VERSION 5.7 ;
  NOWIREEXTENSIONATPIN ON ;
  DIVIDERCHAR "/" ;
  BUSBITCHARS "[]" ;
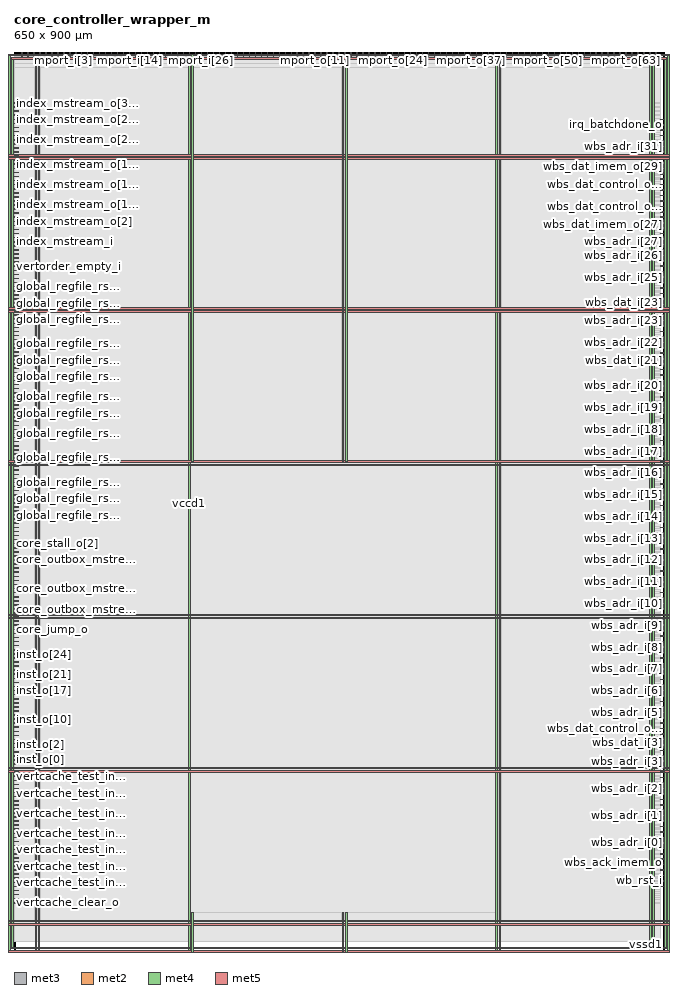
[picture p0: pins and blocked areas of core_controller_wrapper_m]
MACRO core_controller_wrapper_m
  CLASS BLOCK ;
  FOREIGN core_controller_wrapper_m ;
  ORIGIN 0.000 0.000 ;
  SIZE 650.000 BY 900.000 ;
  PIN core_inbox_mstream_i[0]
    DIRECTION INPUT ;
    USE SIGNAL ;
    ANTENNAGATEAREA 0.247500 ;
    PORT
      LAYER met3 ;
        RECT 0.000 326.440 4.000 327.040 ;
    END
  END core_inbox_mstream_i[0]
  PIN core_inbox_mstream_i[1]
    DIRECTION INPUT ;
    USE SIGNAL ;
    ANTENNAGATEAREA 0.247500 ;
    PORT
      LAYER met3 ;
        RECT 0.000 355.000 4.000 355.600 ;
    END
  END core_inbox_mstream_i[1]
  PIN core_inbox_mstream_i[2]
    DIRECTION INPUT ;
    USE SIGNAL ;
    ANTENNAGATEAREA 0.247500 ;
    PORT
      LAYER met3 ;
        RECT 0.000 383.560 4.000 384.160 ;
    END
  END core_inbox_mstream_i[2]
  PIN core_jump_i[0]
    DIRECTION INPUT ;
    USE SIGNAL ;
    ANTENNAGATEAREA 0.196500 ;
    PORT
      LAYER met3 ;
        RECT 0.000 330.520 4.000 331.120 ;
    END
  END core_jump_i[0]
  PIN core_jump_i[1]
    DIRECTION INPUT ;
    USE SIGNAL ;
    ANTENNAGATEAREA 0.196500 ;
    PORT
      LAYER met3 ;
        RECT 0.000 359.080 4.000 359.680 ;
    END
  END core_jump_i[1]
  PIN core_jump_i[2]
    DIRECTION INPUT ;
    USE SIGNAL ;
    ANTENNAGATEAREA 0.196500 ;
    PORT
      LAYER met3 ;
        RECT 0.000 387.640 4.000 388.240 ;
    END
  END core_jump_i[2]
  PIN core_jump_o
    DIRECTION OUTPUT TRISTATE ;
    USE SIGNAL ;
    ANTENNADIFFAREA 0.795200 ;
    PORT
      LAYER met3 ;
        RECT 0.000 322.360 4.000 322.960 ;
    END
  END core_jump_o
  PIN core_outbox_mstream_valid_i[0]
    DIRECTION INPUT ;
    USE SIGNAL ;
    ANTENNAGATEAREA 0.196500 ;
    PORT
      LAYER met3 ;
        RECT 0.000 334.600 4.000 335.200 ;
    END
  END core_outbox_mstream_valid_i[0]
  PIN core_outbox_mstream_valid_i[1]
    DIRECTION INPUT ;
    USE SIGNAL ;
    ANTENNAGATEAREA 0.196500 ;
    PORT
      LAYER met3 ;
        RECT 0.000 363.160 4.000 363.760 ;
    END
  END core_outbox_mstream_valid_i[1]
  PIN core_outbox_mstream_valid_i[2]
    DIRECTION INPUT ;
    USE SIGNAL ;
    ANTENNAGATEAREA 0.196500 ;
    PORT
      LAYER met3 ;
        RECT 0.000 391.720 4.000 392.320 ;
    END
  END core_outbox_mstream_valid_i[2]
  PIN core_reset_mailbox_o[0]
    DIRECTION OUTPUT TRISTATE ;
    USE SIGNAL ;
    ANTENNADIFFAREA 0.795200 ;
    PORT
      LAYER met3 ;
        RECT 0.000 338.680 4.000 339.280 ;
    END
  END core_reset_mailbox_o[0]
  PIN core_reset_mailbox_o[1]
    DIRECTION OUTPUT TRISTATE ;
    USE SIGNAL ;
    ANTENNADIFFAREA 0.795200 ;
    PORT
      LAYER met3 ;
        RECT 0.000 367.240 4.000 367.840 ;
    END
  END core_reset_mailbox_o[1]
  PIN core_reset_mailbox_o[2]
    DIRECTION OUTPUT TRISTATE ;
    USE SIGNAL ;
    ANTENNADIFFAREA 0.795200 ;
    PORT
      LAYER met3 ;
        RECT 0.000 395.800 4.000 396.400 ;
    END
  END core_reset_mailbox_o[2]
  PIN core_reset_o[0]
    DIRECTION OUTPUT TRISTATE ;
    USE SIGNAL ;
    ANTENNADIFFAREA 0.795200 ;
    PORT
      LAYER met3 ;
        RECT 0.000 342.760 4.000 343.360 ;
    END
  END core_reset_o[0]
  PIN core_reset_o[1]
    DIRECTION OUTPUT TRISTATE ;
    USE SIGNAL ;
    ANTENNADIFFAREA 0.795200 ;
    PORT
      LAYER met3 ;
        RECT 0.000 371.320 4.000 371.920 ;
    END
  END core_reset_o[1]
  PIN core_reset_o[2]
    DIRECTION OUTPUT TRISTATE ;
    USE SIGNAL ;
    ANTENNADIFFAREA 0.795200 ;
    PORT
      LAYER met3 ;
        RECT 0.000 399.880 4.000 400.480 ;
    END
  END core_reset_o[2]
  PIN core_stall_i[0]
    DIRECTION INPUT ;
    USE SIGNAL ;
    ANTENNAGATEAREA 0.196500 ;
    PORT
      LAYER met3 ;
        RECT 0.000 346.840 4.000 347.440 ;
    END
  END core_stall_i[0]
  PIN core_stall_i[1]
    DIRECTION INPUT ;
    USE SIGNAL ;
    ANTENNAGATEAREA 0.196500 ;
    PORT
      LAYER met3 ;
        RECT 0.000 375.400 4.000 376.000 ;
    END
  END core_stall_i[1]
  PIN core_stall_i[2]
    DIRECTION INPUT ;
    USE SIGNAL ;
    ANTENNAGATEAREA 0.196500 ;
    PORT
      LAYER met3 ;
        RECT 0.000 403.960 4.000 404.560 ;
    END
  END core_stall_i[2]
  PIN core_stall_o[0]
    DIRECTION OUTPUT TRISTATE ;
    USE SIGNAL ;
    ANTENNADIFFAREA 0.795200 ;
    PORT
      LAYER met3 ;
        RECT 0.000 350.920 4.000 351.520 ;
    END
  END core_stall_o[0]
  PIN core_stall_o[1]
    DIRECTION OUTPUT TRISTATE ;
    USE SIGNAL ;
    ANTENNADIFFAREA 0.795200 ;
    PORT
      LAYER met3 ;
        RECT 0.000 379.480 4.000 380.080 ;
    END
  END core_stall_o[1]
  PIN core_stall_o[2]
    DIRECTION OUTPUT TRISTATE ;
    USE SIGNAL ;
    ANTENNADIFFAREA 0.795200 ;
    PORT
      LAYER met3 ;
        RECT 0.000 408.040 4.000 408.640 ;
    END
  END core_stall_o[2]
  PIN fragfifo_clear_o
    DIRECTION OUTPUT TRISTATE ;
    USE SIGNAL ;
    ANTENNADIFFAREA 0.795200 ;
    PORT
      LAYER met2 ;
        RECT 7.910 896.000 8.190 900.000 ;
    END
  END fragfifo_clear_o
  PIN fragfifo_empty_i
    DIRECTION INPUT ;
    USE SIGNAL ;
    ANTENNAGATEAREA 0.126000 ;
    PORT
      LAYER met2 ;
        RECT 13.890 896.000 14.170 900.000 ;
    END
  END fragfifo_empty_i
  PIN fragfifo_full_i
    DIRECTION INPUT ;
    USE SIGNAL ;
    PORT
      LAYER met2 ;
        RECT 19.870 896.000 20.150 900.000 ;
    END
  END fragfifo_full_i
  PIN global_regfile_rs1_data_o[0]
    DIRECTION OUTPUT TRISTATE ;
    USE SIGNAL ;
    ANTENNADIFFAREA 0.795200 ;
    PORT
      LAYER met3 ;
        RECT 0.000 412.120 4.000 412.720 ;
    END
  END global_regfile_rs1_data_o[0]
  PIN global_regfile_rs1_data_o[10]
    DIRECTION OUTPUT TRISTATE ;
    USE SIGNAL ;
    ANTENNADIFFAREA 0.795200 ;
    PORT
      LAYER met3 ;
        RECT 0.000 493.720 4.000 494.320 ;
    END
  END global_regfile_rs1_data_o[10]
  PIN global_regfile_rs1_data_o[11]
    DIRECTION OUTPUT TRISTATE ;
    USE SIGNAL ;
    ANTENNADIFFAREA 0.795200 ;
    PORT
      LAYER met3 ;
        RECT 0.000 501.880 4.000 502.480 ;
    END
  END global_regfile_rs1_data_o[11]
  PIN global_regfile_rs1_data_o[12]
    DIRECTION OUTPUT TRISTATE ;
    USE SIGNAL ;
    ANTENNADIFFAREA 0.795200 ;
    PORT
      LAYER met3 ;
        RECT 0.000 510.040 4.000 510.640 ;
    END
  END global_regfile_rs1_data_o[12]
  PIN global_regfile_rs1_data_o[13]
    DIRECTION OUTPUT TRISTATE ;
    USE SIGNAL ;
    ANTENNADIFFAREA 0.795200 ;
    PORT
      LAYER met3 ;
        RECT 0.000 518.200 4.000 518.800 ;
    END
  END global_regfile_rs1_data_o[13]
  PIN global_regfile_rs1_data_o[14]
    DIRECTION OUTPUT TRISTATE ;
    USE SIGNAL ;
    ANTENNADIFFAREA 0.795200 ;
    PORT
      LAYER met3 ;
        RECT 0.000 526.360 4.000 526.960 ;
    END
  END global_regfile_rs1_data_o[14]
  PIN global_regfile_rs1_data_o[15]
    DIRECTION OUTPUT TRISTATE ;
    USE SIGNAL ;
    ANTENNADIFFAREA 0.795200 ;
    PORT
      LAYER met3 ;
        RECT 0.000 534.520 4.000 535.120 ;
    END
  END global_regfile_rs1_data_o[15]
  PIN global_regfile_rs1_data_o[16]
    DIRECTION OUTPUT TRISTATE ;
    USE SIGNAL ;
    ANTENNADIFFAREA 0.795200 ;
    PORT
      LAYER met3 ;
        RECT 0.000 542.680 4.000 543.280 ;
    END
  END global_regfile_rs1_data_o[16]
  PIN global_regfile_rs1_data_o[17]
    DIRECTION OUTPUT TRISTATE ;
    USE SIGNAL ;
    ANTENNADIFFAREA 0.795200 ;
    PORT
      LAYER met3 ;
        RECT 0.000 550.840 4.000 551.440 ;
    END
  END global_regfile_rs1_data_o[17]
  PIN global_regfile_rs1_data_o[18]
    DIRECTION OUTPUT TRISTATE ;
    USE SIGNAL ;
    ANTENNADIFFAREA 0.795200 ;
    PORT
      LAYER met3 ;
        RECT 0.000 559.000 4.000 559.600 ;
    END
  END global_regfile_rs1_data_o[18]
  PIN global_regfile_rs1_data_o[19]
    DIRECTION OUTPUT TRISTATE ;
    USE SIGNAL ;
    ANTENNADIFFAREA 0.795200 ;
    PORT
      LAYER met3 ;
        RECT 0.000 567.160 4.000 567.760 ;
    END
  END global_regfile_rs1_data_o[19]
  PIN global_regfile_rs1_data_o[1]
    DIRECTION OUTPUT TRISTATE ;
    USE SIGNAL ;
    ANTENNADIFFAREA 0.795200 ;
    PORT
      LAYER met3 ;
        RECT 0.000 420.280 4.000 420.880 ;
    END
  END global_regfile_rs1_data_o[1]
  PIN global_regfile_rs1_data_o[20]
    DIRECTION OUTPUT TRISTATE ;
    USE SIGNAL ;
    ANTENNADIFFAREA 0.795200 ;
    PORT
      LAYER met3 ;
        RECT 0.000 575.320 4.000 575.920 ;
    END
  END global_regfile_rs1_data_o[20]
  PIN global_regfile_rs1_data_o[21]
    DIRECTION OUTPUT TRISTATE ;
    USE SIGNAL ;
    ANTENNADIFFAREA 0.795200 ;
    PORT
      LAYER met3 ;
        RECT 0.000 583.480 4.000 584.080 ;
    END
  END global_regfile_rs1_data_o[21]
  PIN global_regfile_rs1_data_o[22]
    DIRECTION OUTPUT TRISTATE ;
    USE SIGNAL ;
    ANTENNADIFFAREA 0.795200 ;
    PORT
      LAYER met3 ;
        RECT 0.000 591.640 4.000 592.240 ;
    END
  END global_regfile_rs1_data_o[22]
  PIN global_regfile_rs1_data_o[23]
    DIRECTION OUTPUT TRISTATE ;
    USE SIGNAL ;
    ANTENNADIFFAREA 0.795200 ;
    PORT
      LAYER met3 ;
        RECT 0.000 599.800 4.000 600.400 ;
    END
  END global_regfile_rs1_data_o[23]
  PIN global_regfile_rs1_data_o[24]
    DIRECTION OUTPUT TRISTATE ;
    USE SIGNAL ;
    ANTENNADIFFAREA 0.795200 ;
    PORT
      LAYER met3 ;
        RECT 0.000 607.960 4.000 608.560 ;
    END
  END global_regfile_rs1_data_o[24]
  PIN global_regfile_rs1_data_o[25]
    DIRECTION OUTPUT TRISTATE ;
    USE SIGNAL ;
    ANTENNADIFFAREA 0.795200 ;
    PORT
      LAYER met3 ;
        RECT 0.000 616.120 4.000 616.720 ;
    END
  END global_regfile_rs1_data_o[25]
  PIN global_regfile_rs1_data_o[26]
    DIRECTION OUTPUT TRISTATE ;
    USE SIGNAL ;
    ANTENNADIFFAREA 0.795200 ;
    PORT
      LAYER met3 ;
        RECT 0.000 624.280 4.000 624.880 ;
    END
  END global_regfile_rs1_data_o[26]
  PIN global_regfile_rs1_data_o[27]
    DIRECTION OUTPUT TRISTATE ;
    USE SIGNAL ;
    ANTENNADIFFAREA 0.795200 ;
    PORT
      LAYER met3 ;
        RECT 0.000 632.440 4.000 633.040 ;
    END
  END global_regfile_rs1_data_o[27]
  PIN global_regfile_rs1_data_o[28]
    DIRECTION OUTPUT TRISTATE ;
    USE SIGNAL ;
    ANTENNADIFFAREA 0.795200 ;
    PORT
      LAYER met3 ;
        RECT 0.000 640.600 4.000 641.200 ;
    END
  END global_regfile_rs1_data_o[28]
  PIN global_regfile_rs1_data_o[29]
    DIRECTION OUTPUT TRISTATE ;
    USE SIGNAL ;
    ANTENNADIFFAREA 0.795200 ;
    PORT
      LAYER met3 ;
        RECT 0.000 648.760 4.000 649.360 ;
    END
  END global_regfile_rs1_data_o[29]
  PIN global_regfile_rs1_data_o[2]
    DIRECTION OUTPUT TRISTATE ;
    USE SIGNAL ;
    ANTENNADIFFAREA 0.795200 ;
    PORT
      LAYER met3 ;
        RECT 0.000 428.440 4.000 429.040 ;
    END
  END global_regfile_rs1_data_o[2]
  PIN global_regfile_rs1_data_o[30]
    DIRECTION OUTPUT TRISTATE ;
    USE SIGNAL ;
    ANTENNADIFFAREA 0.795200 ;
    PORT
      LAYER met3 ;
        RECT 0.000 656.920 4.000 657.520 ;
    END
  END global_regfile_rs1_data_o[30]
  PIN global_regfile_rs1_data_o[31]
    DIRECTION OUTPUT TRISTATE ;
    USE SIGNAL ;
    ANTENNADIFFAREA 0.795200 ;
    PORT
      LAYER met3 ;
        RECT 0.000 665.080 4.000 665.680 ;
    END
  END global_regfile_rs1_data_o[31]
  PIN global_regfile_rs1_data_o[3]
    DIRECTION OUTPUT TRISTATE ;
    USE SIGNAL ;
    ANTENNADIFFAREA 0.795200 ;
    PORT
      LAYER met3 ;
        RECT 0.000 436.600 4.000 437.200 ;
    END
  END global_regfile_rs1_data_o[3]
  PIN global_regfile_rs1_data_o[4]
    DIRECTION OUTPUT TRISTATE ;
    USE SIGNAL ;
    ANTENNADIFFAREA 0.795200 ;
    PORT
      LAYER met3 ;
        RECT 0.000 444.760 4.000 445.360 ;
    END
  END global_regfile_rs1_data_o[4]
  PIN global_regfile_rs1_data_o[5]
    DIRECTION OUTPUT TRISTATE ;
    USE SIGNAL ;
    ANTENNADIFFAREA 0.795200 ;
    PORT
      LAYER met3 ;
        RECT 0.000 452.920 4.000 453.520 ;
    END
  END global_regfile_rs1_data_o[5]
  PIN global_regfile_rs1_data_o[6]
    DIRECTION OUTPUT TRISTATE ;
    USE SIGNAL ;
    ANTENNADIFFAREA 0.795200 ;
    PORT
      LAYER met3 ;
        RECT 0.000 461.080 4.000 461.680 ;
    END
  END global_regfile_rs1_data_o[6]
  PIN global_regfile_rs1_data_o[7]
    DIRECTION OUTPUT TRISTATE ;
    USE SIGNAL ;
    ANTENNADIFFAREA 0.795200 ;
    PORT
      LAYER met3 ;
        RECT 0.000 469.240 4.000 469.840 ;
    END
  END global_regfile_rs1_data_o[7]
  PIN global_regfile_rs1_data_o[8]
    DIRECTION OUTPUT TRISTATE ;
    USE SIGNAL ;
    ANTENNADIFFAREA 0.795200 ;
    PORT
      LAYER met3 ;
        RECT 0.000 477.400 4.000 478.000 ;
    END
  END global_regfile_rs1_data_o[8]
  PIN global_regfile_rs1_data_o[9]
    DIRECTION OUTPUT TRISTATE ;
    USE SIGNAL ;
    ANTENNADIFFAREA 0.795200 ;
    PORT
      LAYER met3 ;
        RECT 0.000 485.560 4.000 486.160 ;
    END
  END global_regfile_rs1_data_o[9]
  PIN global_regfile_rs2_data_o[0]
    DIRECTION OUTPUT TRISTATE ;
    USE SIGNAL ;
    ANTENNADIFFAREA 0.795200 ;
    PORT
      LAYER met3 ;
        RECT 0.000 416.200 4.000 416.800 ;
    END
  END global_regfile_rs2_data_o[0]
  PIN global_regfile_rs2_data_o[10]
    DIRECTION OUTPUT TRISTATE ;
    USE SIGNAL ;
    ANTENNADIFFAREA 0.795200 ;
    PORT
      LAYER met3 ;
        RECT 0.000 497.800 4.000 498.400 ;
    END
  END global_regfile_rs2_data_o[10]
  PIN global_regfile_rs2_data_o[11]
    DIRECTION OUTPUT TRISTATE ;
    USE SIGNAL ;
    ANTENNADIFFAREA 0.795200 ;
    PORT
      LAYER met3 ;
        RECT 0.000 505.960 4.000 506.560 ;
    END
  END global_regfile_rs2_data_o[11]
  PIN global_regfile_rs2_data_o[12]
    DIRECTION OUTPUT TRISTATE ;
    USE SIGNAL ;
    ANTENNADIFFAREA 0.795200 ;
    PORT
      LAYER met3 ;
        RECT 0.000 514.120 4.000 514.720 ;
    END
  END global_regfile_rs2_data_o[12]
  PIN global_regfile_rs2_data_o[13]
    DIRECTION OUTPUT TRISTATE ;
    USE SIGNAL ;
    ANTENNADIFFAREA 0.795200 ;
    PORT
      LAYER met3 ;
        RECT 0.000 522.280 4.000 522.880 ;
    END
  END global_regfile_rs2_data_o[13]
  PIN global_regfile_rs2_data_o[14]
    DIRECTION OUTPUT TRISTATE ;
    USE SIGNAL ;
    ANTENNADIFFAREA 0.795200 ;
    PORT
      LAYER met3 ;
        RECT 0.000 530.440 4.000 531.040 ;
    END
  END global_regfile_rs2_data_o[14]
  PIN global_regfile_rs2_data_o[15]
    DIRECTION OUTPUT TRISTATE ;
    USE SIGNAL ;
    ANTENNADIFFAREA 0.795200 ;
    PORT
      LAYER met3 ;
        RECT 0.000 538.600 4.000 539.200 ;
    END
  END global_regfile_rs2_data_o[15]
  PIN global_regfile_rs2_data_o[16]
    DIRECTION OUTPUT TRISTATE ;
    USE SIGNAL ;
    ANTENNADIFFAREA 0.795200 ;
    PORT
      LAYER met3 ;
        RECT 0.000 546.760 4.000 547.360 ;
    END
  END global_regfile_rs2_data_o[16]
  PIN global_regfile_rs2_data_o[17]
    DIRECTION OUTPUT TRISTATE ;
    USE SIGNAL ;
    ANTENNADIFFAREA 0.795200 ;
    PORT
      LAYER met3 ;
        RECT 0.000 554.920 4.000 555.520 ;
    END
  END global_regfile_rs2_data_o[17]
  PIN global_regfile_rs2_data_o[18]
    DIRECTION OUTPUT TRISTATE ;
    USE SIGNAL ;
    ANTENNADIFFAREA 0.795200 ;
    PORT
      LAYER met3 ;
        RECT 0.000 563.080 4.000 563.680 ;
    END
  END global_regfile_rs2_data_o[18]
  PIN global_regfile_rs2_data_o[19]
    DIRECTION OUTPUT TRISTATE ;
    USE SIGNAL ;
    ANTENNADIFFAREA 0.795200 ;
    PORT
      LAYER met3 ;
        RECT 0.000 571.240 4.000 571.840 ;
    END
  END global_regfile_rs2_data_o[19]
  PIN global_regfile_rs2_data_o[1]
    DIRECTION OUTPUT TRISTATE ;
    USE SIGNAL ;
    ANTENNADIFFAREA 0.795200 ;
    PORT
      LAYER met3 ;
        RECT 0.000 424.360 4.000 424.960 ;
    END
  END global_regfile_rs2_data_o[1]
  PIN global_regfile_rs2_data_o[20]
    DIRECTION OUTPUT TRISTATE ;
    USE SIGNAL ;
    ANTENNADIFFAREA 0.795200 ;
    PORT
      LAYER met3 ;
        RECT 0.000 579.400 4.000 580.000 ;
    END
  END global_regfile_rs2_data_o[20]
  PIN global_regfile_rs2_data_o[21]
    DIRECTION OUTPUT TRISTATE ;
    USE SIGNAL ;
    ANTENNADIFFAREA 0.795200 ;
    PORT
      LAYER met3 ;
        RECT 0.000 587.560 4.000 588.160 ;
    END
  END global_regfile_rs2_data_o[21]
  PIN global_regfile_rs2_data_o[22]
    DIRECTION OUTPUT TRISTATE ;
    USE SIGNAL ;
    ANTENNADIFFAREA 0.795200 ;
    PORT
      LAYER met3 ;
        RECT 0.000 595.720 4.000 596.320 ;
    END
  END global_regfile_rs2_data_o[22]
  PIN global_regfile_rs2_data_o[23]
    DIRECTION OUTPUT TRISTATE ;
    USE SIGNAL ;
    ANTENNADIFFAREA 0.795200 ;
    PORT
      LAYER met3 ;
        RECT 0.000 603.880 4.000 604.480 ;
    END
  END global_regfile_rs2_data_o[23]
  PIN global_regfile_rs2_data_o[24]
    DIRECTION OUTPUT TRISTATE ;
    USE SIGNAL ;
    ANTENNADIFFAREA 0.795200 ;
    PORT
      LAYER met3 ;
        RECT 0.000 612.040 4.000 612.640 ;
    END
  END global_regfile_rs2_data_o[24]
  PIN global_regfile_rs2_data_o[25]
    DIRECTION OUTPUT TRISTATE ;
    USE SIGNAL ;
    ANTENNADIFFAREA 0.795200 ;
    PORT
      LAYER met3 ;
        RECT 0.000 620.200 4.000 620.800 ;
    END
  END global_regfile_rs2_data_o[25]
  PIN global_regfile_rs2_data_o[26]
    DIRECTION OUTPUT TRISTATE ;
    USE SIGNAL ;
    ANTENNADIFFAREA 0.795200 ;
    PORT
      LAYER met3 ;
        RECT 0.000 628.360 4.000 628.960 ;
    END
  END global_regfile_rs2_data_o[26]
  PIN global_regfile_rs2_data_o[27]
    DIRECTION OUTPUT TRISTATE ;
    USE SIGNAL ;
    ANTENNADIFFAREA 0.795200 ;
    PORT
      LAYER met3 ;
        RECT 0.000 636.520 4.000 637.120 ;
    END
  END global_regfile_rs2_data_o[27]
  PIN global_regfile_rs2_data_o[28]
    DIRECTION OUTPUT TRISTATE ;
    USE SIGNAL ;
    ANTENNADIFFAREA 0.795200 ;
    PORT
      LAYER met3 ;
        RECT 0.000 644.680 4.000 645.280 ;
    END
  END global_regfile_rs2_data_o[28]
  PIN global_regfile_rs2_data_o[29]
    DIRECTION OUTPUT TRISTATE ;
    USE SIGNAL ;
    ANTENNADIFFAREA 0.795200 ;
    PORT
      LAYER met3 ;
        RECT 0.000 652.840 4.000 653.440 ;
    END
  END global_regfile_rs2_data_o[29]
  PIN global_regfile_rs2_data_o[2]
    DIRECTION OUTPUT TRISTATE ;
    USE SIGNAL ;
    ANTENNADIFFAREA 0.795200 ;
    PORT
      LAYER met3 ;
        RECT 0.000 432.520 4.000 433.120 ;
    END
  END global_regfile_rs2_data_o[2]
  PIN global_regfile_rs2_data_o[30]
    DIRECTION OUTPUT TRISTATE ;
    USE SIGNAL ;
    ANTENNADIFFAREA 0.795200 ;
    PORT
      LAYER met3 ;
        RECT 0.000 661.000 4.000 661.600 ;
    END
  END global_regfile_rs2_data_o[30]
  PIN global_regfile_rs2_data_o[31]
    DIRECTION OUTPUT TRISTATE ;
    USE SIGNAL ;
    ANTENNADIFFAREA 0.795200 ;
    PORT
      LAYER met3 ;
        RECT 0.000 669.160 4.000 669.760 ;
    END
  END global_regfile_rs2_data_o[31]
  PIN global_regfile_rs2_data_o[3]
    DIRECTION OUTPUT TRISTATE ;
    USE SIGNAL ;
    ANTENNADIFFAREA 0.795200 ;
    PORT
      LAYER met3 ;
        RECT 0.000 440.680 4.000 441.280 ;
    END
  END global_regfile_rs2_data_o[3]
  PIN global_regfile_rs2_data_o[4]
    DIRECTION OUTPUT TRISTATE ;
    USE SIGNAL ;
    ANTENNADIFFAREA 0.795200 ;
    PORT
      LAYER met3 ;
        RECT 0.000 448.840 4.000 449.440 ;
    END
  END global_regfile_rs2_data_o[4]
  PIN global_regfile_rs2_data_o[5]
    DIRECTION OUTPUT TRISTATE ;
    USE SIGNAL ;
    ANTENNADIFFAREA 0.795200 ;
    PORT
      LAYER met3 ;
        RECT 0.000 457.000 4.000 457.600 ;
    END
  END global_regfile_rs2_data_o[5]
  PIN global_regfile_rs2_data_o[6]
    DIRECTION OUTPUT TRISTATE ;
    USE SIGNAL ;
    ANTENNADIFFAREA 0.795200 ;
    PORT
      LAYER met3 ;
        RECT 0.000 465.160 4.000 465.760 ;
    END
  END global_regfile_rs2_data_o[6]
  PIN global_regfile_rs2_data_o[7]
    DIRECTION OUTPUT TRISTATE ;
    USE SIGNAL ;
    ANTENNADIFFAREA 0.795200 ;
    PORT
      LAYER met3 ;
        RECT 0.000 473.320 4.000 473.920 ;
    END
  END global_regfile_rs2_data_o[7]
  PIN global_regfile_rs2_data_o[8]
    DIRECTION OUTPUT TRISTATE ;
    USE SIGNAL ;
    ANTENNADIFFAREA 0.795200 ;
    PORT
      LAYER met3 ;
        RECT 0.000 481.480 4.000 482.080 ;
    END
  END global_regfile_rs2_data_o[8]
  PIN global_regfile_rs2_data_o[9]
    DIRECTION OUTPUT TRISTATE ;
    USE SIGNAL ;
    ANTENNADIFFAREA 0.795200 ;
    PORT
      LAYER met3 ;
        RECT 0.000 489.640 4.000 490.240 ;
    END
  END global_regfile_rs2_data_o[9]
  PIN index_mstream_i
    DIRECTION INPUT ;
    USE SIGNAL ;
    PORT
      LAYER met3 ;
        RECT 0.000 709.960 4.000 710.560 ;
    END
  END index_mstream_i
  PIN index_mstream_o[0]
    DIRECTION OUTPUT TRISTATE ;
    USE SIGNAL ;
    ANTENNADIFFAREA 0.795200 ;
    PORT
      LAYER met3 ;
        RECT 0.000 714.040 4.000 714.640 ;
    END
  END index_mstream_o[0]
  PIN index_mstream_o[10]
    DIRECTION OUTPUT TRISTATE ;
    USE SIGNAL ;
    ANTENNADIFFAREA 0.795200 ;
    PORT
      LAYER met3 ;
        RECT 0.000 754.840 4.000 755.440 ;
    END
  END index_mstream_o[10]
  PIN index_mstream_o[11]
    DIRECTION OUTPUT TRISTATE ;
    USE SIGNAL ;
    ANTENNADIFFAREA 0.795200 ;
    PORT
      LAYER met3 ;
        RECT 0.000 758.920 4.000 759.520 ;
    END
  END index_mstream_o[11]
  PIN index_mstream_o[12]
    DIRECTION OUTPUT TRISTATE ;
    USE SIGNAL ;
    ANTENNADIFFAREA 0.795200 ;
    PORT
      LAYER met3 ;
        RECT 0.000 763.000 4.000 763.600 ;
    END
  END index_mstream_o[12]
  PIN index_mstream_o[13]
    DIRECTION OUTPUT TRISTATE ;
    USE SIGNAL ;
    ANTENNADIFFAREA 0.795200 ;
    PORT
      LAYER met3 ;
        RECT 0.000 767.080 4.000 767.680 ;
    END
  END index_mstream_o[13]
  PIN index_mstream_o[14]
    DIRECTION OUTPUT TRISTATE ;
    USE SIGNAL ;
    ANTENNADIFFAREA 0.795200 ;
    PORT
      LAYER met3 ;
        RECT 0.000 771.160 4.000 771.760 ;
    END
  END index_mstream_o[14]
  PIN index_mstream_o[15]
    DIRECTION OUTPUT TRISTATE ;
    USE SIGNAL ;
    ANTENNADIFFAREA 0.795200 ;
    PORT
      LAYER met3 ;
        RECT 0.000 775.240 4.000 775.840 ;
    END
  END index_mstream_o[15]
  PIN index_mstream_o[16]
    DIRECTION OUTPUT TRISTATE ;
    USE SIGNAL ;
    ANTENNADIFFAREA 0.795200 ;
    PORT
      LAYER met3 ;
        RECT 0.000 779.320 4.000 779.920 ;
    END
  END index_mstream_o[16]
  PIN index_mstream_o[17]
    DIRECTION OUTPUT TRISTATE ;
    USE SIGNAL ;
    ANTENNADIFFAREA 0.795200 ;
    PORT
      LAYER met3 ;
        RECT 0.000 783.400 4.000 784.000 ;
    END
  END index_mstream_o[17]
  PIN index_mstream_o[18]
    DIRECTION OUTPUT TRISTATE ;
    USE SIGNAL ;
    ANTENNADIFFAREA 0.795200 ;
    PORT
      LAYER met3 ;
        RECT 0.000 787.480 4.000 788.080 ;
    END
  END index_mstream_o[18]
  PIN index_mstream_o[19]
    DIRECTION OUTPUT TRISTATE ;
    USE SIGNAL ;
    ANTENNADIFFAREA 0.795200 ;
    PORT
      LAYER met3 ;
        RECT 0.000 791.560 4.000 792.160 ;
    END
  END index_mstream_o[19]
  PIN index_mstream_o[1]
    DIRECTION OUTPUT TRISTATE ;
    USE SIGNAL ;
    ANTENNADIFFAREA 0.795200 ;
    PORT
      LAYER met3 ;
        RECT 0.000 718.120 4.000 718.720 ;
    END
  END index_mstream_o[1]
  PIN index_mstream_o[20]
    DIRECTION OUTPUT TRISTATE ;
    USE SIGNAL ;
    ANTENNADIFFAREA 0.795200 ;
    PORT
      LAYER met3 ;
        RECT 0.000 795.640 4.000 796.240 ;
    END
  END index_mstream_o[20]
  PIN index_mstream_o[21]
    DIRECTION OUTPUT TRISTATE ;
    USE SIGNAL ;
    ANTENNADIFFAREA 0.795200 ;
    PORT
      LAYER met3 ;
        RECT 0.000 799.720 4.000 800.320 ;
    END
  END index_mstream_o[21]
  PIN index_mstream_o[22]
    DIRECTION OUTPUT TRISTATE ;
    USE SIGNAL ;
    ANTENNADIFFAREA 0.795200 ;
    PORT
      LAYER met3 ;
        RECT 0.000 803.800 4.000 804.400 ;
    END
  END index_mstream_o[22]
  PIN index_mstream_o[23]
    DIRECTION OUTPUT TRISTATE ;
    USE SIGNAL ;
    ANTENNADIFFAREA 0.795200 ;
    PORT
      LAYER met3 ;
        RECT 0.000 807.880 4.000 808.480 ;
    END
  END index_mstream_o[23]
  PIN index_mstream_o[24]
    DIRECTION OUTPUT TRISTATE ;
    USE SIGNAL ;
    ANTENNADIFFAREA 0.795200 ;
    PORT
      LAYER met3 ;
        RECT 0.000 811.960 4.000 812.560 ;
    END
  END index_mstream_o[24]
  PIN index_mstream_o[25]
    DIRECTION OUTPUT TRISTATE ;
    USE SIGNAL ;
    ANTENNADIFFAREA 0.795200 ;
    PORT
      LAYER met3 ;
        RECT 0.000 816.040 4.000 816.640 ;
    END
  END index_mstream_o[25]
  PIN index_mstream_o[26]
    DIRECTION OUTPUT TRISTATE ;
    USE SIGNAL ;
    ANTENNADIFFAREA 0.795200 ;
    PORT
      LAYER met3 ;
        RECT 0.000 820.120 4.000 820.720 ;
    END
  END index_mstream_o[26]
  PIN index_mstream_o[27]
    DIRECTION OUTPUT TRISTATE ;
    USE SIGNAL ;
    ANTENNADIFFAREA 0.795200 ;
    PORT
      LAYER met3 ;
        RECT 0.000 824.200 4.000 824.800 ;
    END
  END index_mstream_o[27]
  PIN index_mstream_o[28]
    DIRECTION OUTPUT TRISTATE ;
    USE SIGNAL ;
    ANTENNADIFFAREA 0.795200 ;
    PORT
      LAYER met3 ;
        RECT 0.000 828.280 4.000 828.880 ;
    END
  END index_mstream_o[28]
  PIN index_mstream_o[29]
    DIRECTION OUTPUT TRISTATE ;
    USE SIGNAL ;
    ANTENNADIFFAREA 0.795200 ;
    PORT
      LAYER met3 ;
        RECT 0.000 832.360 4.000 832.960 ;
    END
  END index_mstream_o[29]
  PIN index_mstream_o[2]
    DIRECTION OUTPUT TRISTATE ;
    USE SIGNAL ;
    ANTENNADIFFAREA 0.795200 ;
    PORT
      LAYER met3 ;
        RECT 0.000 722.200 4.000 722.800 ;
    END
  END index_mstream_o[2]
  PIN index_mstream_o[30]
    DIRECTION OUTPUT TRISTATE ;
    USE SIGNAL ;
    ANTENNADIFFAREA 0.795200 ;
    PORT
      LAYER met3 ;
        RECT 0.000 836.440 4.000 837.040 ;
    END
  END index_mstream_o[30]
  PIN index_mstream_o[31]
    DIRECTION OUTPUT TRISTATE ;
    USE SIGNAL ;
    ANTENNADIFFAREA 0.795200 ;
    PORT
      LAYER met3 ;
        RECT 0.000 840.520 4.000 841.120 ;
    END
  END index_mstream_o[31]
  PIN index_mstream_o[32]
    DIRECTION OUTPUT TRISTATE ;
    USE SIGNAL ;
    ANTENNADIFFAREA 0.795200 ;
    PORT
      LAYER met3 ;
        RECT 0.000 844.600 4.000 845.200 ;
    END
  END index_mstream_o[32]
  PIN index_mstream_o[33]
    DIRECTION OUTPUT TRISTATE ;
    USE SIGNAL ;
    PORT
      LAYER met3 ;
        RECT 0.000 848.680 4.000 849.280 ;
    END
  END index_mstream_o[33]
  PIN index_mstream_o[3]
    DIRECTION OUTPUT TRISTATE ;
    USE SIGNAL ;
    ANTENNADIFFAREA 0.795200 ;
    PORT
      LAYER met3 ;
        RECT 0.000 726.280 4.000 726.880 ;
    END
  END index_mstream_o[3]
  PIN index_mstream_o[4]
    DIRECTION OUTPUT TRISTATE ;
    USE SIGNAL ;
    ANTENNADIFFAREA 0.795200 ;
    PORT
      LAYER met3 ;
        RECT 0.000 730.360 4.000 730.960 ;
    END
  END index_mstream_o[4]
  PIN index_mstream_o[5]
    DIRECTION OUTPUT TRISTATE ;
    USE SIGNAL ;
    ANTENNADIFFAREA 0.795200 ;
    PORT
      LAYER met3 ;
        RECT 0.000 734.440 4.000 735.040 ;
    END
  END index_mstream_o[5]
  PIN index_mstream_o[6]
    DIRECTION OUTPUT TRISTATE ;
    USE SIGNAL ;
    ANTENNADIFFAREA 0.795200 ;
    PORT
      LAYER met3 ;
        RECT 0.000 738.520 4.000 739.120 ;
    END
  END index_mstream_o[6]
  PIN index_mstream_o[7]
    DIRECTION OUTPUT TRISTATE ;
    USE SIGNAL ;
    ANTENNADIFFAREA 0.795200 ;
    PORT
      LAYER met3 ;
        RECT 0.000 742.600 4.000 743.200 ;
    END
  END index_mstream_o[7]
  PIN index_mstream_o[8]
    DIRECTION OUTPUT TRISTATE ;
    USE SIGNAL ;
    ANTENNADIFFAREA 0.795200 ;
    PORT
      LAYER met3 ;
        RECT 0.000 746.680 4.000 747.280 ;
    END
  END index_mstream_o[8]
  PIN index_mstream_o[9]
    DIRECTION OUTPUT TRISTATE ;
    USE SIGNAL ;
    ANTENNADIFFAREA 0.795200 ;
    PORT
      LAYER met3 ;
        RECT 0.000 750.760 4.000 751.360 ;
    END
  END index_mstream_o[9]
  PIN inst_o[0]
    DIRECTION OUTPUT TRISTATE ;
    USE SIGNAL ;
    ANTENNADIFFAREA 0.795200 ;
    PORT
      LAYER met3 ;
        RECT 0.000 191.800 4.000 192.400 ;
    END
  END inst_o[0]
  PIN inst_o[10]
    DIRECTION OUTPUT TRISTATE ;
    USE SIGNAL ;
    ANTENNADIFFAREA 0.795200 ;
    PORT
      LAYER met3 ;
        RECT 0.000 232.600 4.000 233.200 ;
    END
  END inst_o[10]
  PIN inst_o[11]
    DIRECTION OUTPUT TRISTATE ;
    USE SIGNAL ;
    ANTENNADIFFAREA 0.795200 ;
    PORT
      LAYER met3 ;
        RECT 0.000 236.680 4.000 237.280 ;
    END
  END inst_o[11]
  PIN inst_o[12]
    DIRECTION OUTPUT TRISTATE ;
    USE SIGNAL ;
    ANTENNADIFFAREA 0.795200 ;
    PORT
      LAYER met3 ;
        RECT 0.000 240.760 4.000 241.360 ;
    END
  END inst_o[12]
  PIN inst_o[13]
    DIRECTION OUTPUT TRISTATE ;
    USE SIGNAL ;
    ANTENNADIFFAREA 0.795200 ;
    PORT
      LAYER met3 ;
        RECT 0.000 244.840 4.000 245.440 ;
    END
  END inst_o[13]
  PIN inst_o[14]
    DIRECTION OUTPUT TRISTATE ;
    USE SIGNAL ;
    ANTENNADIFFAREA 0.795200 ;
    PORT
      LAYER met3 ;
        RECT 0.000 248.920 4.000 249.520 ;
    END
  END inst_o[14]
  PIN inst_o[15]
    DIRECTION OUTPUT TRISTATE ;
    USE SIGNAL ;
    ANTENNADIFFAREA 0.795200 ;
    PORT
      LAYER met3 ;
        RECT 0.000 253.000 4.000 253.600 ;
    END
  END inst_o[15]
  PIN inst_o[16]
    DIRECTION OUTPUT TRISTATE ;
    USE SIGNAL ;
    ANTENNADIFFAREA 0.795200 ;
    PORT
      LAYER met3 ;
        RECT 0.000 257.080 4.000 257.680 ;
    END
  END inst_o[16]
  PIN inst_o[17]
    DIRECTION OUTPUT TRISTATE ;
    USE SIGNAL ;
    ANTENNADIFFAREA 0.795200 ;
    PORT
      LAYER met3 ;
        RECT 0.000 261.160 4.000 261.760 ;
    END
  END inst_o[17]
  PIN inst_o[18]
    DIRECTION OUTPUT TRISTATE ;
    USE SIGNAL ;
    ANTENNADIFFAREA 0.795200 ;
    PORT
      LAYER met3 ;
        RECT 0.000 265.240 4.000 265.840 ;
    END
  END inst_o[18]
  PIN inst_o[19]
    DIRECTION OUTPUT TRISTATE ;
    USE SIGNAL ;
    ANTENNADIFFAREA 0.795200 ;
    PORT
      LAYER met3 ;
        RECT 0.000 269.320 4.000 269.920 ;
    END
  END inst_o[19]
  PIN inst_o[1]
    DIRECTION OUTPUT TRISTATE ;
    USE SIGNAL ;
    ANTENNADIFFAREA 0.795200 ;
    PORT
      LAYER met3 ;
        RECT 0.000 195.880 4.000 196.480 ;
    END
  END inst_o[1]
  PIN inst_o[20]
    DIRECTION OUTPUT TRISTATE ;
    USE SIGNAL ;
    ANTENNADIFFAREA 0.795200 ;
    PORT
      LAYER met3 ;
        RECT 0.000 273.400 4.000 274.000 ;
    END
  END inst_o[20]
  PIN inst_o[21]
    DIRECTION OUTPUT TRISTATE ;
    USE SIGNAL ;
    ANTENNADIFFAREA 0.795200 ;
    PORT
      LAYER met3 ;
        RECT 0.000 277.480 4.000 278.080 ;
    END
  END inst_o[21]
  PIN inst_o[22]
    DIRECTION OUTPUT TRISTATE ;
    USE SIGNAL ;
    ANTENNADIFFAREA 0.795200 ;
    PORT
      LAYER met3 ;
        RECT 0.000 281.560 4.000 282.160 ;
    END
  END inst_o[22]
  PIN inst_o[23]
    DIRECTION OUTPUT TRISTATE ;
    USE SIGNAL ;
    ANTENNADIFFAREA 0.795200 ;
    PORT
      LAYER met3 ;
        RECT 0.000 285.640 4.000 286.240 ;
    END
  END inst_o[23]
  PIN inst_o[24]
    DIRECTION OUTPUT TRISTATE ;
    USE SIGNAL ;
    ANTENNADIFFAREA 0.795200 ;
    PORT
      LAYER met3 ;
        RECT 0.000 289.720 4.000 290.320 ;
    END
  END inst_o[24]
  PIN inst_o[25]
    DIRECTION OUTPUT TRISTATE ;
    USE SIGNAL ;
    ANTENNADIFFAREA 0.795200 ;
    PORT
      LAYER met3 ;
        RECT 0.000 293.800 4.000 294.400 ;
    END
  END inst_o[25]
  PIN inst_o[26]
    DIRECTION OUTPUT TRISTATE ;
    USE SIGNAL ;
    ANTENNADIFFAREA 0.795200 ;
    PORT
      LAYER met3 ;
        RECT 0.000 297.880 4.000 298.480 ;
    END
  END inst_o[26]
  PIN inst_o[27]
    DIRECTION OUTPUT TRISTATE ;
    USE SIGNAL ;
    ANTENNADIFFAREA 0.795200 ;
    PORT
      LAYER met3 ;
        RECT 0.000 301.960 4.000 302.560 ;
    END
  END inst_o[27]
  PIN inst_o[28]
    DIRECTION OUTPUT TRISTATE ;
    USE SIGNAL ;
    ANTENNADIFFAREA 0.795200 ;
    PORT
      LAYER met3 ;
        RECT 0.000 306.040 4.000 306.640 ;
    END
  END inst_o[28]
  PIN inst_o[29]
    DIRECTION OUTPUT TRISTATE ;
    USE SIGNAL ;
    ANTENNADIFFAREA 0.795200 ;
    PORT
      LAYER met3 ;
        RECT 0.000 310.120 4.000 310.720 ;
    END
  END inst_o[29]
  PIN inst_o[2]
    DIRECTION OUTPUT TRISTATE ;
    USE SIGNAL ;
    ANTENNADIFFAREA 0.795200 ;
    PORT
      LAYER met3 ;
        RECT 0.000 199.960 4.000 200.560 ;
    END
  END inst_o[2]
  PIN inst_o[30]
    DIRECTION OUTPUT TRISTATE ;
    USE SIGNAL ;
    ANTENNADIFFAREA 0.795200 ;
    PORT
      LAYER met3 ;
        RECT 0.000 314.200 4.000 314.800 ;
    END
  END inst_o[30]
  PIN inst_o[31]
    DIRECTION OUTPUT TRISTATE ;
    USE SIGNAL ;
    ANTENNADIFFAREA 0.795200 ;
    PORT
      LAYER met3 ;
        RECT 0.000 318.280 4.000 318.880 ;
    END
  END inst_o[31]
  PIN inst_o[3]
    DIRECTION OUTPUT TRISTATE ;
    USE SIGNAL ;
    ANTENNADIFFAREA 0.795200 ;
    PORT
      LAYER met3 ;
        RECT 0.000 204.040 4.000 204.640 ;
    END
  END inst_o[3]
  PIN inst_o[4]
    DIRECTION OUTPUT TRISTATE ;
    USE SIGNAL ;
    ANTENNADIFFAREA 0.795200 ;
    PORT
      LAYER met3 ;
        RECT 0.000 208.120 4.000 208.720 ;
    END
  END inst_o[4]
  PIN inst_o[5]
    DIRECTION OUTPUT TRISTATE ;
    USE SIGNAL ;
    ANTENNADIFFAREA 0.795200 ;
    PORT
      LAYER met3 ;
        RECT 0.000 212.200 4.000 212.800 ;
    END
  END inst_o[5]
  PIN inst_o[6]
    DIRECTION OUTPUT TRISTATE ;
    USE SIGNAL ;
    ANTENNADIFFAREA 0.795200 ;
    PORT
      LAYER met3 ;
        RECT 0.000 216.280 4.000 216.880 ;
    END
  END inst_o[6]
  PIN inst_o[7]
    DIRECTION OUTPUT TRISTATE ;
    USE SIGNAL ;
    ANTENNADIFFAREA 0.795200 ;
    PORT
      LAYER met3 ;
        RECT 0.000 220.360 4.000 220.960 ;
    END
  END inst_o[7]
  PIN inst_o[8]
    DIRECTION OUTPUT TRISTATE ;
    USE SIGNAL ;
    ANTENNADIFFAREA 0.795200 ;
    PORT
      LAYER met3 ;
        RECT 0.000 224.440 4.000 225.040 ;
    END
  END inst_o[8]
  PIN inst_o[9]
    DIRECTION OUTPUT TRISTATE ;
    USE SIGNAL ;
    ANTENNADIFFAREA 0.795200 ;
    PORT
      LAYER met3 ;
        RECT 0.000 228.520 4.000 229.120 ;
    END
  END inst_o[9]
  PIN irq_batchdone_o
    DIRECTION OUTPUT TRISTATE ;
    USE SIGNAL ;
    ANTENNADIFFAREA 0.795200 ;
    PORT
      LAYER met3 ;
        RECT 646.000 826.920 650.000 827.520 ;
    END
  END irq_batchdone_o
  PIN irq_jobdone_o
    DIRECTION OUTPUT TRISTATE ;
    USE SIGNAL ;
    ANTENNADIFFAREA 0.445500 ;
    PORT
      LAYER met3 ;
        RECT 646.000 832.360 650.000 832.960 ;
    END
  END irq_jobdone_o
  PIN mport_i[0]
    DIRECTION INPUT ;
    USE SIGNAL ;
    ANTENNAGATEAREA 0.196500 ;
    PORT
      LAYER met2 ;
        RECT 31.830 896.000 32.110 900.000 ;
    END
  END mport_i[0]
  PIN mport_i[10]
    DIRECTION INPUT ;
    USE SIGNAL ;
    ANTENNAGATEAREA 0.196500 ;
    PORT
      LAYER met2 ;
        RECT 91.630 896.000 91.910 900.000 ;
    END
  END mport_i[10]
  PIN mport_i[11]
    DIRECTION INPUT ;
    USE SIGNAL ;
    ANTENNAGATEAREA 0.196500 ;
    PORT
      LAYER met2 ;
        RECT 97.610 896.000 97.890 900.000 ;
    END
  END mport_i[11]
  PIN mport_i[12]
    DIRECTION INPUT ;
    USE SIGNAL ;
    ANTENNAGATEAREA 0.196500 ;
    PORT
      LAYER met2 ;
        RECT 103.590 896.000 103.870 900.000 ;
    END
  END mport_i[12]
  PIN mport_i[13]
    DIRECTION INPUT ;
    USE SIGNAL ;
    ANTENNAGATEAREA 0.196500 ;
    PORT
      LAYER met2 ;
        RECT 109.570 896.000 109.850 900.000 ;
    END
  END mport_i[13]
  PIN mport_i[14]
    DIRECTION INPUT ;
    USE SIGNAL ;
    ANTENNAGATEAREA 0.196500 ;
    PORT
      LAYER met2 ;
        RECT 115.550 896.000 115.830 900.000 ;
    END
  END mport_i[14]
  PIN mport_i[15]
    DIRECTION INPUT ;
    USE SIGNAL ;
    ANTENNAGATEAREA 0.196500 ;
    PORT
      LAYER met2 ;
        RECT 121.530 896.000 121.810 900.000 ;
    END
  END mport_i[15]
  PIN mport_i[16]
    DIRECTION INPUT ;
    USE SIGNAL ;
    ANTENNAGATEAREA 0.196500 ;
    PORT
      LAYER met2 ;
        RECT 127.510 896.000 127.790 900.000 ;
    END
  END mport_i[16]
  PIN mport_i[17]
    DIRECTION INPUT ;
    USE SIGNAL ;
    ANTENNAGATEAREA 0.196500 ;
    PORT
      LAYER met2 ;
        RECT 133.490 896.000 133.770 900.000 ;
    END
  END mport_i[17]
  PIN mport_i[18]
    DIRECTION INPUT ;
    USE SIGNAL ;
    ANTENNAGATEAREA 0.196500 ;
    PORT
      LAYER met2 ;
        RECT 139.470 896.000 139.750 900.000 ;
    END
  END mport_i[18]
  PIN mport_i[19]
    DIRECTION INPUT ;
    USE SIGNAL ;
    ANTENNAGATEAREA 0.196500 ;
    PORT
      LAYER met2 ;
        RECT 145.450 896.000 145.730 900.000 ;
    END
  END mport_i[19]
  PIN mport_i[1]
    DIRECTION INPUT ;
    USE SIGNAL ;
    ANTENNAGATEAREA 0.196500 ;
    PORT
      LAYER met2 ;
        RECT 37.810 896.000 38.090 900.000 ;
    END
  END mport_i[1]
  PIN mport_i[20]
    DIRECTION INPUT ;
    USE SIGNAL ;
    ANTENNAGATEAREA 0.196500 ;
    PORT
      LAYER met2 ;
        RECT 151.430 896.000 151.710 900.000 ;
    END
  END mport_i[20]
  PIN mport_i[21]
    DIRECTION INPUT ;
    USE SIGNAL ;
    ANTENNAGATEAREA 0.196500 ;
    PORT
      LAYER met2 ;
        RECT 157.410 896.000 157.690 900.000 ;
    END
  END mport_i[21]
  PIN mport_i[22]
    DIRECTION INPUT ;
    USE SIGNAL ;
    ANTENNAGATEAREA 0.196500 ;
    PORT
      LAYER met2 ;
        RECT 163.390 896.000 163.670 900.000 ;
    END
  END mport_i[22]
  PIN mport_i[23]
    DIRECTION INPUT ;
    USE SIGNAL ;
    ANTENNAGATEAREA 0.196500 ;
    PORT
      LAYER met2 ;
        RECT 169.370 896.000 169.650 900.000 ;
    END
  END mport_i[23]
  PIN mport_i[24]
    DIRECTION INPUT ;
    USE SIGNAL ;
    ANTENNAGATEAREA 0.196500 ;
    PORT
      LAYER met2 ;
        RECT 175.350 896.000 175.630 900.000 ;
    END
  END mport_i[24]
  PIN mport_i[25]
    DIRECTION INPUT ;
    USE SIGNAL ;
    ANTENNAGATEAREA 0.213000 ;
    PORT
      LAYER met2 ;
        RECT 181.330 896.000 181.610 900.000 ;
    END
  END mport_i[25]
  PIN mport_i[26]
    DIRECTION INPUT ;
    USE SIGNAL ;
    ANTENNAGATEAREA 0.126000 ;
    PORT
      LAYER met2 ;
        RECT 187.310 896.000 187.590 900.000 ;
    END
  END mport_i[26]
  PIN mport_i[27]
    DIRECTION INPUT ;
    USE SIGNAL ;
    ANTENNAGATEAREA 0.196500 ;
    PORT
      LAYER met2 ;
        RECT 193.290 896.000 193.570 900.000 ;
    END
  END mport_i[27]
  PIN mport_i[28]
    DIRECTION INPUT ;
    USE SIGNAL ;
    ANTENNAGATEAREA 0.159000 ;
    PORT
      LAYER met2 ;
        RECT 199.270 896.000 199.550 900.000 ;
    END
  END mport_i[28]
  PIN mport_i[29]
    DIRECTION INPUT ;
    USE SIGNAL ;
    ANTENNAGATEAREA 0.213000 ;
    PORT
      LAYER met2 ;
        RECT 205.250 896.000 205.530 900.000 ;
    END
  END mport_i[29]
  PIN mport_i[2]
    DIRECTION INPUT ;
    USE SIGNAL ;
    ANTENNAGATEAREA 0.196500 ;
    PORT
      LAYER met2 ;
        RECT 43.790 896.000 44.070 900.000 ;
    END
  END mport_i[2]
  PIN mport_i[30]
    DIRECTION INPUT ;
    USE SIGNAL ;
    ANTENNAGATEAREA 0.213000 ;
    PORT
      LAYER met2 ;
        RECT 211.230 896.000 211.510 900.000 ;
    END
  END mport_i[30]
  PIN mport_i[31]
    DIRECTION INPUT ;
    USE SIGNAL ;
    ANTENNAGATEAREA 0.213000 ;
    PORT
      LAYER met2 ;
        RECT 217.210 896.000 217.490 900.000 ;
    END
  END mport_i[31]
  PIN mport_i[32]
    DIRECTION INPUT ;
    USE SIGNAL ;
    ANTENNAGATEAREA 0.426000 ;
    PORT
      LAYER met2 ;
        RECT 223.190 896.000 223.470 900.000 ;
    END
  END mport_i[32]
  PIN mport_i[33]
    DIRECTION INPUT ;
    USE SIGNAL ;
    ANTENNAGATEAREA 0.495000 ;
    PORT
      LAYER met2 ;
        RECT 229.170 896.000 229.450 900.000 ;
    END
  END mport_i[33]
  PIN mport_i[3]
    DIRECTION INPUT ;
    USE SIGNAL ;
    ANTENNAGATEAREA 0.196500 ;
    PORT
      LAYER met2 ;
        RECT 49.770 896.000 50.050 900.000 ;
    END
  END mport_i[3]
  PIN mport_i[4]
    DIRECTION INPUT ;
    USE SIGNAL ;
    ANTENNAGATEAREA 0.196500 ;
    PORT
      LAYER met2 ;
        RECT 55.750 896.000 56.030 900.000 ;
    END
  END mport_i[4]
  PIN mport_i[5]
    DIRECTION INPUT ;
    USE SIGNAL ;
    ANTENNAGATEAREA 0.196500 ;
    PORT
      LAYER met2 ;
        RECT 61.730 896.000 62.010 900.000 ;
    END
  END mport_i[5]
  PIN mport_i[6]
    DIRECTION INPUT ;
    USE SIGNAL ;
    ANTENNAGATEAREA 0.196500 ;
    PORT
      LAYER met2 ;
        RECT 67.710 896.000 67.990 900.000 ;
    END
  END mport_i[6]
  PIN mport_i[7]
    DIRECTION INPUT ;
    USE SIGNAL ;
    ANTENNAGATEAREA 0.196500 ;
    PORT
      LAYER met2 ;
        RECT 73.690 896.000 73.970 900.000 ;
    END
  END mport_i[7]
  PIN mport_i[8]
    DIRECTION INPUT ;
    USE SIGNAL ;
    ANTENNAGATEAREA 0.196500 ;
    PORT
      LAYER met2 ;
        RECT 79.670 896.000 79.950 900.000 ;
    END
  END mport_i[8]
  PIN mport_i[9]
    DIRECTION INPUT ;
    USE SIGNAL ;
    ANTENNAGATEAREA 0.196500 ;
    PORT
      LAYER met2 ;
        RECT 85.650 896.000 85.930 900.000 ;
    END
  END mport_i[9]
  PIN mport_o[0]
    DIRECTION OUTPUT TRISTATE ;
    USE SIGNAL ;
    PORT
      LAYER met2 ;
        RECT 235.150 896.000 235.430 900.000 ;
    END
  END mport_o[0]
  PIN mport_o[10]
    DIRECTION OUTPUT TRISTATE ;
    USE SIGNAL ;
    PORT
      LAYER met2 ;
        RECT 294.950 896.000 295.230 900.000 ;
    END
  END mport_o[10]
  PIN mport_o[11]
    DIRECTION OUTPUT TRISTATE ;
    USE SIGNAL ;
    PORT
      LAYER met2 ;
        RECT 300.930 896.000 301.210 900.000 ;
    END
  END mport_o[11]
  PIN mport_o[12]
    DIRECTION OUTPUT TRISTATE ;
    USE SIGNAL ;
    PORT
      LAYER met2 ;
        RECT 306.910 896.000 307.190 900.000 ;
    END
  END mport_o[12]
  PIN mport_o[13]
    DIRECTION OUTPUT TRISTATE ;
    USE SIGNAL ;
    PORT
      LAYER met2 ;
        RECT 312.890 896.000 313.170 900.000 ;
    END
  END mport_o[13]
  PIN mport_o[14]
    DIRECTION OUTPUT TRISTATE ;
    USE SIGNAL ;
    PORT
      LAYER met2 ;
        RECT 318.870 896.000 319.150 900.000 ;
    END
  END mport_o[14]
  PIN mport_o[15]
    DIRECTION OUTPUT TRISTATE ;
    USE SIGNAL ;
    PORT
      LAYER met2 ;
        RECT 324.850 896.000 325.130 900.000 ;
    END
  END mport_o[15]
  PIN mport_o[16]
    DIRECTION OUTPUT TRISTATE ;
    USE SIGNAL ;
    PORT
      LAYER met2 ;
        RECT 330.830 896.000 331.110 900.000 ;
    END
  END mport_o[16]
  PIN mport_o[17]
    DIRECTION OUTPUT TRISTATE ;
    USE SIGNAL ;
    PORT
      LAYER met2 ;
        RECT 336.810 896.000 337.090 900.000 ;
    END
  END mport_o[17]
  PIN mport_o[18]
    DIRECTION OUTPUT TRISTATE ;
    USE SIGNAL ;
    PORT
      LAYER met2 ;
        RECT 342.790 896.000 343.070 900.000 ;
    END
  END mport_o[18]
  PIN mport_o[19]
    DIRECTION OUTPUT TRISTATE ;
    USE SIGNAL ;
    PORT
      LAYER met2 ;
        RECT 348.770 896.000 349.050 900.000 ;
    END
  END mport_o[19]
  PIN mport_o[1]
    DIRECTION OUTPUT TRISTATE ;
    USE SIGNAL ;
    PORT
      LAYER met2 ;
        RECT 241.130 896.000 241.410 900.000 ;
    END
  END mport_o[1]
  PIN mport_o[20]
    DIRECTION OUTPUT TRISTATE ;
    USE SIGNAL ;
    PORT
      LAYER met2 ;
        RECT 354.750 896.000 355.030 900.000 ;
    END
  END mport_o[20]
  PIN mport_o[21]
    DIRECTION OUTPUT TRISTATE ;
    USE SIGNAL ;
    PORT
      LAYER met2 ;
        RECT 360.730 896.000 361.010 900.000 ;
    END
  END mport_o[21]
  PIN mport_o[22]
    DIRECTION OUTPUT TRISTATE ;
    USE SIGNAL ;
    PORT
      LAYER met2 ;
        RECT 366.710 896.000 366.990 900.000 ;
    END
  END mport_o[22]
  PIN mport_o[23]
    DIRECTION OUTPUT TRISTATE ;
    USE SIGNAL ;
    PORT
      LAYER met2 ;
        RECT 372.690 896.000 372.970 900.000 ;
    END
  END mport_o[23]
  PIN mport_o[24]
    DIRECTION OUTPUT TRISTATE ;
    USE SIGNAL ;
    PORT
      LAYER met2 ;
        RECT 378.670 896.000 378.950 900.000 ;
    END
  END mport_o[24]
  PIN mport_o[25]
    DIRECTION OUTPUT TRISTATE ;
    USE SIGNAL ;
    PORT
      LAYER met2 ;
        RECT 384.650 896.000 384.930 900.000 ;
    END
  END mport_o[25]
  PIN mport_o[26]
    DIRECTION OUTPUT TRISTATE ;
    USE SIGNAL ;
    PORT
      LAYER met2 ;
        RECT 390.630 896.000 390.910 900.000 ;
    END
  END mport_o[26]
  PIN mport_o[27]
    DIRECTION OUTPUT TRISTATE ;
    USE SIGNAL ;
    PORT
      LAYER met2 ;
        RECT 396.610 896.000 396.890 900.000 ;
    END
  END mport_o[27]
  PIN mport_o[28]
    DIRECTION OUTPUT TRISTATE ;
    USE SIGNAL ;
    PORT
      LAYER met2 ;
        RECT 402.590 896.000 402.870 900.000 ;
    END
  END mport_o[28]
  PIN mport_o[29]
    DIRECTION OUTPUT TRISTATE ;
    USE SIGNAL ;
    PORT
      LAYER met2 ;
        RECT 408.570 896.000 408.850 900.000 ;
    END
  END mport_o[29]
  PIN mport_o[2]
    DIRECTION OUTPUT TRISTATE ;
    USE SIGNAL ;
    PORT
      LAYER met2 ;
        RECT 247.110 896.000 247.390 900.000 ;
    END
  END mport_o[2]
  PIN mport_o[30]
    DIRECTION OUTPUT TRISTATE ;
    USE SIGNAL ;
    PORT
      LAYER met2 ;
        RECT 414.550 896.000 414.830 900.000 ;
    END
  END mport_o[30]
  PIN mport_o[31]
    DIRECTION OUTPUT TRISTATE ;
    USE SIGNAL ;
    PORT
      LAYER met2 ;
        RECT 420.530 896.000 420.810 900.000 ;
    END
  END mport_o[31]
  PIN mport_o[32]
    DIRECTION OUTPUT TRISTATE ;
    USE SIGNAL ;
    ANTENNADIFFAREA 0.795200 ;
    PORT
      LAYER met2 ;
        RECT 426.510 896.000 426.790 900.000 ;
    END
  END mport_o[32]
  PIN mport_o[33]
    DIRECTION OUTPUT TRISTATE ;
    USE SIGNAL ;
    ANTENNADIFFAREA 0.795200 ;
    PORT
      LAYER met2 ;
        RECT 432.490 896.000 432.770 900.000 ;
    END
  END mport_o[33]
  PIN mport_o[34]
    DIRECTION OUTPUT TRISTATE ;
    USE SIGNAL ;
    ANTENNADIFFAREA 0.445500 ;
    PORT
      LAYER met2 ;
        RECT 438.470 896.000 438.750 900.000 ;
    END
  END mport_o[34]
  PIN mport_o[35]
    DIRECTION OUTPUT TRISTATE ;
    USE SIGNAL ;
    ANTENNADIFFAREA 0.795200 ;
    PORT
      LAYER met2 ;
        RECT 444.450 896.000 444.730 900.000 ;
    END
  END mport_o[35]
  PIN mport_o[36]
    DIRECTION OUTPUT TRISTATE ;
    USE SIGNAL ;
    ANTENNADIFFAREA 0.795200 ;
    PORT
      LAYER met2 ;
        RECT 450.430 896.000 450.710 900.000 ;
    END
  END mport_o[36]
  PIN mport_o[37]
    DIRECTION OUTPUT TRISTATE ;
    USE SIGNAL ;
    ANTENNADIFFAREA 0.795200 ;
    PORT
      LAYER met2 ;
        RECT 456.410 896.000 456.690 900.000 ;
    END
  END mport_o[37]
  PIN mport_o[38]
    DIRECTION OUTPUT TRISTATE ;
    USE SIGNAL ;
    ANTENNADIFFAREA 0.795200 ;
    PORT
      LAYER met2 ;
        RECT 462.390 896.000 462.670 900.000 ;
    END
  END mport_o[38]
  PIN mport_o[39]
    DIRECTION OUTPUT TRISTATE ;
    USE SIGNAL ;
    ANTENNADIFFAREA 0.795200 ;
    PORT
      LAYER met2 ;
        RECT 468.370 896.000 468.650 900.000 ;
    END
  END mport_o[39]
  PIN mport_o[3]
    DIRECTION OUTPUT TRISTATE ;
    USE SIGNAL ;
    PORT
      LAYER met2 ;
        RECT 253.090 896.000 253.370 900.000 ;
    END
  END mport_o[3]
  PIN mport_o[40]
    DIRECTION OUTPUT TRISTATE ;
    USE SIGNAL ;
    ANTENNADIFFAREA 0.795200 ;
    PORT
      LAYER met2 ;
        RECT 474.350 896.000 474.630 900.000 ;
    END
  END mport_o[40]
  PIN mport_o[41]
    DIRECTION OUTPUT TRISTATE ;
    USE SIGNAL ;
    ANTENNADIFFAREA 0.795200 ;
    PORT
      LAYER met2 ;
        RECT 480.330 896.000 480.610 900.000 ;
    END
  END mport_o[41]
  PIN mport_o[42]
    DIRECTION OUTPUT TRISTATE ;
    USE SIGNAL ;
    ANTENNADIFFAREA 0.445500 ;
    PORT
      LAYER met2 ;
        RECT 486.310 896.000 486.590 900.000 ;
    END
  END mport_o[42]
  PIN mport_o[43]
    DIRECTION OUTPUT TRISTATE ;
    USE SIGNAL ;
    ANTENNADIFFAREA 0.795200 ;
    PORT
      LAYER met2 ;
        RECT 492.290 896.000 492.570 900.000 ;
    END
  END mport_o[43]
  PIN mport_o[44]
    DIRECTION OUTPUT TRISTATE ;
    USE SIGNAL ;
    ANTENNADIFFAREA 0.795200 ;
    PORT
      LAYER met2 ;
        RECT 498.270 896.000 498.550 900.000 ;
    END
  END mport_o[44]
  PIN mport_o[45]
    DIRECTION OUTPUT TRISTATE ;
    USE SIGNAL ;
    ANTENNADIFFAREA 0.795200 ;
    PORT
      LAYER met2 ;
        RECT 504.250 896.000 504.530 900.000 ;
    END
  END mport_o[45]
  PIN mport_o[46]
    DIRECTION OUTPUT TRISTATE ;
    USE SIGNAL ;
    ANTENNADIFFAREA 0.795200 ;
    PORT
      LAYER met2 ;
        RECT 510.230 896.000 510.510 900.000 ;
    END
  END mport_o[46]
  PIN mport_o[47]
    DIRECTION OUTPUT TRISTATE ;
    USE SIGNAL ;
    ANTENNADIFFAREA 0.795200 ;
    PORT
      LAYER met2 ;
        RECT 516.210 896.000 516.490 900.000 ;
    END
  END mport_o[47]
  PIN mport_o[48]
    DIRECTION OUTPUT TRISTATE ;
    USE SIGNAL ;
    ANTENNADIFFAREA 0.795200 ;
    PORT
      LAYER met2 ;
        RECT 522.190 896.000 522.470 900.000 ;
    END
  END mport_o[48]
  PIN mport_o[49]
    DIRECTION OUTPUT TRISTATE ;
    USE SIGNAL ;
    ANTENNADIFFAREA 0.445500 ;
    PORT
      LAYER met2 ;
        RECT 528.170 896.000 528.450 900.000 ;
    END
  END mport_o[49]
  PIN mport_o[4]
    DIRECTION OUTPUT TRISTATE ;
    USE SIGNAL ;
    PORT
      LAYER met2 ;
        RECT 259.070 896.000 259.350 900.000 ;
    END
  END mport_o[4]
  PIN mport_o[50]
    DIRECTION OUTPUT TRISTATE ;
    USE SIGNAL ;
    ANTENNADIFFAREA 0.795200 ;
    PORT
      LAYER met2 ;
        RECT 534.150 896.000 534.430 900.000 ;
    END
  END mport_o[50]
  PIN mport_o[51]
    DIRECTION OUTPUT TRISTATE ;
    USE SIGNAL ;
    ANTENNADIFFAREA 0.795200 ;
    PORT
      LAYER met2 ;
        RECT 540.130 896.000 540.410 900.000 ;
    END
  END mport_o[51]
  PIN mport_o[52]
    DIRECTION OUTPUT TRISTATE ;
    USE SIGNAL ;
    ANTENNADIFFAREA 0.795200 ;
    PORT
      LAYER met2 ;
        RECT 546.110 896.000 546.390 900.000 ;
    END
  END mport_o[52]
  PIN mport_o[53]
    DIRECTION OUTPUT TRISTATE ;
    USE SIGNAL ;
    ANTENNADIFFAREA 0.795200 ;
    PORT
      LAYER met2 ;
        RECT 552.090 896.000 552.370 900.000 ;
    END
  END mport_o[53]
  PIN mport_o[54]
    DIRECTION OUTPUT TRISTATE ;
    USE SIGNAL ;
    ANTENNADIFFAREA 0.795200 ;
    PORT
      LAYER met2 ;
        RECT 558.070 896.000 558.350 900.000 ;
    END
  END mport_o[54]
  PIN mport_o[55]
    DIRECTION OUTPUT TRISTATE ;
    USE SIGNAL ;
    ANTENNADIFFAREA 0.795200 ;
    PORT
      LAYER met2 ;
        RECT 564.050 896.000 564.330 900.000 ;
    END
  END mport_o[55]
  PIN mport_o[56]
    DIRECTION OUTPUT TRISTATE ;
    USE SIGNAL ;
    ANTENNADIFFAREA 0.795200 ;
    PORT
      LAYER met2 ;
        RECT 570.030 896.000 570.310 900.000 ;
    END
  END mport_o[56]
  PIN mport_o[57]
    DIRECTION OUTPUT TRISTATE ;
    USE SIGNAL ;
    ANTENNADIFFAREA 0.795200 ;
    PORT
      LAYER met2 ;
        RECT 576.010 896.000 576.290 900.000 ;
    END
  END mport_o[57]
  PIN mport_o[58]
    DIRECTION OUTPUT TRISTATE ;
    USE SIGNAL ;
    ANTENNADIFFAREA 0.445500 ;
    PORT
      LAYER met2 ;
        RECT 581.990 896.000 582.270 900.000 ;
    END
  END mport_o[58]
  PIN mport_o[59]
    DIRECTION OUTPUT TRISTATE ;
    USE SIGNAL ;
    ANTENNADIFFAREA 0.795200 ;
    PORT
      LAYER met2 ;
        RECT 587.970 896.000 588.250 900.000 ;
    END
  END mport_o[59]
  PIN mport_o[5]
    DIRECTION OUTPUT TRISTATE ;
    USE SIGNAL ;
    PORT
      LAYER met2 ;
        RECT 265.050 896.000 265.330 900.000 ;
    END
  END mport_o[5]
  PIN mport_o[60]
    DIRECTION OUTPUT TRISTATE ;
    USE SIGNAL ;
    ANTENNADIFFAREA 0.795200 ;
    PORT
      LAYER met2 ;
        RECT 593.950 896.000 594.230 900.000 ;
    END
  END mport_o[60]
  PIN mport_o[61]
    DIRECTION OUTPUT TRISTATE ;
    USE SIGNAL ;
    ANTENNADIFFAREA 0.795200 ;
    PORT
      LAYER met2 ;
        RECT 599.930 896.000 600.210 900.000 ;
    END
  END mport_o[61]
  PIN mport_o[62]
    DIRECTION OUTPUT TRISTATE ;
    USE SIGNAL ;
    ANTENNADIFFAREA 0.795200 ;
    PORT
      LAYER met2 ;
        RECT 605.910 896.000 606.190 900.000 ;
    END
  END mport_o[62]
  PIN mport_o[63]
    DIRECTION OUTPUT TRISTATE ;
    USE SIGNAL ;
    ANTENNADIFFAREA 0.795200 ;
    PORT
      LAYER met2 ;
        RECT 611.890 896.000 612.170 900.000 ;
    END
  END mport_o[63]
  PIN mport_o[64]
    DIRECTION OUTPUT TRISTATE ;
    USE SIGNAL ;
    ANTENNADIFFAREA 0.795200 ;
    PORT
      LAYER met2 ;
        RECT 617.870 896.000 618.150 900.000 ;
    END
  END mport_o[64]
  PIN mport_o[65]
    DIRECTION OUTPUT TRISTATE ;
    USE SIGNAL ;
    ANTENNADIFFAREA 0.795200 ;
    PORT
      LAYER met2 ;
        RECT 623.850 896.000 624.130 900.000 ;
    END
  END mport_o[65]
  PIN mport_o[66]
    DIRECTION OUTPUT TRISTATE ;
    USE SIGNAL ;
    ANTENNADIFFAREA 0.795200 ;
    PORT
      LAYER met2 ;
        RECT 629.830 896.000 630.110 900.000 ;
    END
  END mport_o[66]
  PIN mport_o[67]
    DIRECTION OUTPUT TRISTATE ;
    USE SIGNAL ;
    ANTENNADIFFAREA 0.795200 ;
    PORT
      LAYER met2 ;
        RECT 635.810 896.000 636.090 900.000 ;
    END
  END mport_o[67]
  PIN mport_o[68]
    DIRECTION OUTPUT TRISTATE ;
    USE SIGNAL ;
    PORT
      LAYER met2 ;
        RECT 641.790 896.000 642.070 900.000 ;
    END
  END mport_o[68]
  PIN mport_o[6]
    DIRECTION OUTPUT TRISTATE ;
    USE SIGNAL ;
    PORT
      LAYER met2 ;
        RECT 271.030 896.000 271.310 900.000 ;
    END
  END mport_o[6]
  PIN mport_o[7]
    DIRECTION OUTPUT TRISTATE ;
    USE SIGNAL ;
    PORT
      LAYER met2 ;
        RECT 277.010 896.000 277.290 900.000 ;
    END
  END mport_o[7]
  PIN mport_o[8]
    DIRECTION OUTPUT TRISTATE ;
    USE SIGNAL ;
    PORT
      LAYER met2 ;
        RECT 282.990 896.000 283.270 900.000 ;
    END
  END mport_o[8]
  PIN mport_o[9]
    DIRECTION OUTPUT TRISTATE ;
    USE SIGNAL ;
    PORT
      LAYER met2 ;
        RECT 288.970 896.000 289.250 900.000 ;
    END
  END mport_o[9]
  PIN rast_busy_i
    DIRECTION INPUT ;
    USE SIGNAL ;
    ANTENNAGATEAREA 0.213000 ;
    PORT
      LAYER met2 ;
        RECT 25.850 896.000 26.130 900.000 ;
    END
  END rast_busy_i
  PIN vccd1
    DIRECTION INOUT ;
    USE POWER ;
    PORT
      LAYER met4 ;
        RECT -2.080 3.280 -0.480 894.320 ;
    END
    PORT
      LAYER met5 ;
        RECT -2.080 3.280 652.060 4.880 ;
    END
    PORT
      LAYER met5 ;
        RECT -2.080 892.720 652.060 894.320 ;
    END
    PORT
      LAYER met4 ;
        RECT 650.460 3.280 652.060 894.320 ;
    END
    PORT
      LAYER met4 ;
        RECT 21.040 -0.020 22.640 897.620 ;
    END
    PORT
      LAYER met4 ;
        RECT 174.640 -0.020 176.240 897.620 ;
    END
    PORT
      LAYER met4 ;
        RECT 328.240 -0.020 329.840 39.300 ;
    END
    PORT
      LAYER met4 ;
        RECT 328.240 490.700 329.840 897.620 ;
    END
    PORT
      LAYER met4 ;
        RECT 481.840 -0.020 483.440 897.620 ;
    END
    PORT
      LAYER met4 ;
        RECT 635.440 -0.020 637.040 897.620 ;
    END
    PORT
      LAYER met5 ;
        RECT -5.380 26.730 655.360 28.330 ;
    END
    PORT
      LAYER met5 ;
        RECT -5.380 179.910 655.360 181.510 ;
    END
    PORT
      LAYER met5 ;
        RECT -5.380 333.090 655.360 334.690 ;
    END
    PORT
      LAYER met5 ;
        RECT -5.380 486.270 655.360 487.870 ;
    END
    PORT
      LAYER met5 ;
        RECT -5.380 639.450 655.360 641.050 ;
    END
    PORT
      LAYER met5 ;
        RECT -5.380 792.630 655.360 794.230 ;
    END
  END vccd1
  PIN vertcache_clear_o
    DIRECTION OUTPUT TRISTATE ;
    USE SIGNAL ;
    ANTENNADIFFAREA 0.795200 ;
    PORT
      LAYER met3 ;
        RECT 0.000 49.000 4.000 49.600 ;
    END
  END vertcache_clear_o
  PIN vertcache_test_found_i
    DIRECTION INPUT ;
    USE SIGNAL ;
    ANTENNAGATEAREA 0.196500 ;
    PORT
      LAYER met3 ;
        RECT 0.000 53.080 4.000 53.680 ;
    END
  END vertcache_test_found_i
  PIN vertcache_test_index_o[0]
    DIRECTION OUTPUT TRISTATE ;
    USE SIGNAL ;
    ANTENNADIFFAREA 0.795200 ;
    PORT
      LAYER met3 ;
        RECT 0.000 61.240 4.000 61.840 ;
    END
  END vertcache_test_index_o[0]
  PIN vertcache_test_index_o[10]
    DIRECTION OUTPUT TRISTATE ;
    USE SIGNAL ;
    ANTENNADIFFAREA 0.795200 ;
    PORT
      LAYER met3 ;
        RECT 0.000 102.040 4.000 102.640 ;
    END
  END vertcache_test_index_o[10]
  PIN vertcache_test_index_o[11]
    DIRECTION OUTPUT TRISTATE ;
    USE SIGNAL ;
    ANTENNADIFFAREA 0.795200 ;
    PORT
      LAYER met3 ;
        RECT 0.000 106.120 4.000 106.720 ;
    END
  END vertcache_test_index_o[11]
  PIN vertcache_test_index_o[12]
    DIRECTION OUTPUT TRISTATE ;
    USE SIGNAL ;
    ANTENNADIFFAREA 0.795200 ;
    PORT
      LAYER met3 ;
        RECT 0.000 110.200 4.000 110.800 ;
    END
  END vertcache_test_index_o[12]
  PIN vertcache_test_index_o[13]
    DIRECTION OUTPUT TRISTATE ;
    USE SIGNAL ;
    ANTENNADIFFAREA 0.795200 ;
    PORT
      LAYER met3 ;
        RECT 0.000 114.280 4.000 114.880 ;
    END
  END vertcache_test_index_o[13]
  PIN vertcache_test_index_o[14]
    DIRECTION OUTPUT TRISTATE ;
    USE SIGNAL ;
    ANTENNADIFFAREA 0.795200 ;
    PORT
      LAYER met3 ;
        RECT 0.000 118.360 4.000 118.960 ;
    END
  END vertcache_test_index_o[14]
  PIN vertcache_test_index_o[15]
    DIRECTION OUTPUT TRISTATE ;
    USE SIGNAL ;
    ANTENNADIFFAREA 0.795200 ;
    PORT
      LAYER met3 ;
        RECT 0.000 122.440 4.000 123.040 ;
    END
  END vertcache_test_index_o[15]
  PIN vertcache_test_index_o[16]
    DIRECTION OUTPUT TRISTATE ;
    USE SIGNAL ;
    ANTENNADIFFAREA 0.795200 ;
    PORT
      LAYER met3 ;
        RECT 0.000 126.520 4.000 127.120 ;
    END
  END vertcache_test_index_o[16]
  PIN vertcache_test_index_o[17]
    DIRECTION OUTPUT TRISTATE ;
    USE SIGNAL ;
    ANTENNADIFFAREA 0.795200 ;
    PORT
      LAYER met3 ;
        RECT 0.000 130.600 4.000 131.200 ;
    END
  END vertcache_test_index_o[17]
  PIN vertcache_test_index_o[18]
    DIRECTION OUTPUT TRISTATE ;
    USE SIGNAL ;
    ANTENNADIFFAREA 0.795200 ;
    PORT
      LAYER met3 ;
        RECT 0.000 134.680 4.000 135.280 ;
    END
  END vertcache_test_index_o[18]
  PIN vertcache_test_index_o[19]
    DIRECTION OUTPUT TRISTATE ;
    USE SIGNAL ;
    ANTENNADIFFAREA 0.795200 ;
    PORT
      LAYER met3 ;
        RECT 0.000 138.760 4.000 139.360 ;
    END
  END vertcache_test_index_o[19]
  PIN vertcache_test_index_o[1]
    DIRECTION OUTPUT TRISTATE ;
    USE SIGNAL ;
    ANTENNADIFFAREA 0.795200 ;
    PORT
      LAYER met3 ;
        RECT 0.000 65.320 4.000 65.920 ;
    END
  END vertcache_test_index_o[1]
  PIN vertcache_test_index_o[20]
    DIRECTION OUTPUT TRISTATE ;
    USE SIGNAL ;
    ANTENNADIFFAREA 0.795200 ;
    PORT
      LAYER met3 ;
        RECT 0.000 142.840 4.000 143.440 ;
    END
  END vertcache_test_index_o[20]
  PIN vertcache_test_index_o[21]
    DIRECTION OUTPUT TRISTATE ;
    USE SIGNAL ;
    ANTENNADIFFAREA 0.795200 ;
    PORT
      LAYER met3 ;
        RECT 0.000 146.920 4.000 147.520 ;
    END
  END vertcache_test_index_o[21]
  PIN vertcache_test_index_o[22]
    DIRECTION OUTPUT TRISTATE ;
    USE SIGNAL ;
    ANTENNADIFFAREA 0.795200 ;
    PORT
      LAYER met3 ;
        RECT 0.000 151.000 4.000 151.600 ;
    END
  END vertcache_test_index_o[22]
  PIN vertcache_test_index_o[23]
    DIRECTION OUTPUT TRISTATE ;
    USE SIGNAL ;
    ANTENNADIFFAREA 0.795200 ;
    PORT
      LAYER met3 ;
        RECT 0.000 155.080 4.000 155.680 ;
    END
  END vertcache_test_index_o[23]
  PIN vertcache_test_index_o[24]
    DIRECTION OUTPUT TRISTATE ;
    USE SIGNAL ;
    ANTENNADIFFAREA 0.795200 ;
    PORT
      LAYER met3 ;
        RECT 0.000 159.160 4.000 159.760 ;
    END
  END vertcache_test_index_o[24]
  PIN vertcache_test_index_o[25]
    DIRECTION OUTPUT TRISTATE ;
    USE SIGNAL ;
    ANTENNADIFFAREA 0.795200 ;
    PORT
      LAYER met3 ;
        RECT 0.000 163.240 4.000 163.840 ;
    END
  END vertcache_test_index_o[25]
  PIN vertcache_test_index_o[26]
    DIRECTION OUTPUT TRISTATE ;
    USE SIGNAL ;
    ANTENNADIFFAREA 0.795200 ;
    PORT
      LAYER met3 ;
        RECT 0.000 167.320 4.000 167.920 ;
    END
  END vertcache_test_index_o[26]
  PIN vertcache_test_index_o[27]
    DIRECTION OUTPUT TRISTATE ;
    USE SIGNAL ;
    ANTENNADIFFAREA 0.795200 ;
    PORT
      LAYER met3 ;
        RECT 0.000 171.400 4.000 172.000 ;
    END
  END vertcache_test_index_o[27]
  PIN vertcache_test_index_o[28]
    DIRECTION OUTPUT TRISTATE ;
    USE SIGNAL ;
    ANTENNADIFFAREA 0.795200 ;
    PORT
      LAYER met3 ;
        RECT 0.000 175.480 4.000 176.080 ;
    END
  END vertcache_test_index_o[28]
  PIN vertcache_test_index_o[29]
    DIRECTION OUTPUT TRISTATE ;
    USE SIGNAL ;
    ANTENNADIFFAREA 0.795200 ;
    PORT
      LAYER met3 ;
        RECT 0.000 179.560 4.000 180.160 ;
    END
  END vertcache_test_index_o[29]
  PIN vertcache_test_index_o[2]
    DIRECTION OUTPUT TRISTATE ;
    USE SIGNAL ;
    ANTENNADIFFAREA 0.795200 ;
    PORT
      LAYER met3 ;
        RECT 0.000 69.400 4.000 70.000 ;
    END
  END vertcache_test_index_o[2]
  PIN vertcache_test_index_o[30]
    DIRECTION OUTPUT TRISTATE ;
    USE SIGNAL ;
    ANTENNADIFFAREA 0.795200 ;
    PORT
      LAYER met3 ;
        RECT 0.000 183.640 4.000 184.240 ;
    END
  END vertcache_test_index_o[30]
  PIN vertcache_test_index_o[31]
    DIRECTION OUTPUT TRISTATE ;
    USE SIGNAL ;
    ANTENNADIFFAREA 0.795200 ;
    PORT
      LAYER met3 ;
        RECT 0.000 187.720 4.000 188.320 ;
    END
  END vertcache_test_index_o[31]
  PIN vertcache_test_index_o[3]
    DIRECTION OUTPUT TRISTATE ;
    USE SIGNAL ;
    ANTENNADIFFAREA 0.795200 ;
    PORT
      LAYER met3 ;
        RECT 0.000 73.480 4.000 74.080 ;
    END
  END vertcache_test_index_o[3]
  PIN vertcache_test_index_o[4]
    DIRECTION OUTPUT TRISTATE ;
    USE SIGNAL ;
    ANTENNADIFFAREA 0.795200 ;
    PORT
      LAYER met3 ;
        RECT 0.000 77.560 4.000 78.160 ;
    END
  END vertcache_test_index_o[4]
  PIN vertcache_test_index_o[5]
    DIRECTION OUTPUT TRISTATE ;
    USE SIGNAL ;
    ANTENNADIFFAREA 0.795200 ;
    PORT
      LAYER met3 ;
        RECT 0.000 81.640 4.000 82.240 ;
    END
  END vertcache_test_index_o[5]
  PIN vertcache_test_index_o[6]
    DIRECTION OUTPUT TRISTATE ;
    USE SIGNAL ;
    ANTENNADIFFAREA 0.795200 ;
    PORT
      LAYER met3 ;
        RECT 0.000 85.720 4.000 86.320 ;
    END
  END vertcache_test_index_o[6]
  PIN vertcache_test_index_o[7]
    DIRECTION OUTPUT TRISTATE ;
    USE SIGNAL ;
    ANTENNADIFFAREA 0.795200 ;
    PORT
      LAYER met3 ;
        RECT 0.000 89.800 4.000 90.400 ;
    END
  END vertcache_test_index_o[7]
  PIN vertcache_test_index_o[8]
    DIRECTION OUTPUT TRISTATE ;
    USE SIGNAL ;
    ANTENNADIFFAREA 0.795200 ;
    PORT
      LAYER met3 ;
        RECT 0.000 93.880 4.000 94.480 ;
    END
  END vertcache_test_index_o[8]
  PIN vertcache_test_index_o[9]
    DIRECTION OUTPUT TRISTATE ;
    USE SIGNAL ;
    ANTENNADIFFAREA 0.795200 ;
    PORT
      LAYER met3 ;
        RECT 0.000 97.960 4.000 98.560 ;
    END
  END vertcache_test_index_o[9]
  PIN vertcache_test_valid_o
    DIRECTION OUTPUT TRISTATE ;
    USE SIGNAL ;
    ANTENNADIFFAREA 0.795200 ;
    PORT
      LAYER met3 ;
        RECT 0.000 57.160 4.000 57.760 ;
    END
  END vertcache_test_valid_o
  PIN vertcont_busy_i
    DIRECTION INPUT ;
    USE SIGNAL ;
    ANTENNAGATEAREA 0.196500 ;
    PORT
      LAYER met3 ;
        RECT 0.000 705.880 4.000 706.480 ;
    END
  END vertcont_busy_i
  PIN vertorder_clear_o
    DIRECTION OUTPUT TRISTATE ;
    USE SIGNAL ;
    ANTENNADIFFAREA 0.795200 ;
    PORT
      LAYER met3 ;
        RECT 0.000 673.240 4.000 673.840 ;
    END
  END vertorder_clear_o
  PIN vertorder_empty_i
    DIRECTION INPUT ;
    USE SIGNAL ;
    ANTENNAGATEAREA 0.196500 ;
    PORT
      LAYER met3 ;
        RECT 0.000 677.320 4.000 677.920 ;
    END
  END vertorder_empty_i
  PIN vertorder_full_i
    DIRECTION INPUT ;
    USE SIGNAL ;
    ANTENNAGATEAREA 0.247500 ;
    PORT
      LAYER met3 ;
        RECT 0.000 681.400 4.000 682.000 ;
    END
  END vertorder_full_i
  PIN vertorder_mstream_i
    DIRECTION INPUT ;
    USE SIGNAL ;
    PORT
      LAYER met3 ;
        RECT 0.000 685.480 4.000 686.080 ;
    END
  END vertorder_mstream_i
  PIN vertorder_mstream_o[0]
    DIRECTION OUTPUT TRISTATE ;
    USE SIGNAL ;
    ANTENNADIFFAREA 0.795200 ;
    PORT
      LAYER met3 ;
        RECT 0.000 689.560 4.000 690.160 ;
    END
  END vertorder_mstream_o[0]
  PIN vertorder_mstream_o[1]
    DIRECTION OUTPUT TRISTATE ;
    USE SIGNAL ;
    ANTENNADIFFAREA 0.795200 ;
    PORT
      LAYER met3 ;
        RECT 0.000 693.640 4.000 694.240 ;
    END
  END vertorder_mstream_o[1]
  PIN vertorder_mstream_o[2]
    DIRECTION OUTPUT TRISTATE ;
    USE SIGNAL ;
    ANTENNADIFFAREA 0.795200 ;
    PORT
      LAYER met3 ;
        RECT 0.000 697.720 4.000 698.320 ;
    END
  END vertorder_mstream_o[2]
  PIN vertorder_mstream_o[3]
    DIRECTION OUTPUT TRISTATE ;
    USE SIGNAL ;
    PORT
      LAYER met3 ;
        RECT 0.000 701.800 4.000 702.400 ;
    END
  END vertorder_mstream_o[3]
  PIN vssd1
    DIRECTION INOUT ;
    USE GROUND ;
    PORT
      LAYER met4 ;
        RECT -5.380 -0.020 -3.780 897.620 ;
    END
    PORT
      LAYER met5 ;
        RECT -5.380 -0.020 655.360 1.580 ;
    END
    PORT
      LAYER met5 ;
        RECT -5.380 896.020 655.360 897.620 ;
    END
    PORT
      LAYER met4 ;
        RECT 653.760 -0.020 655.360 897.620 ;
    END
    PORT
      LAYER met4 ;
        RECT 24.340 -0.020 25.940 897.620 ;
    END
    PORT
      LAYER met4 ;
        RECT 177.940 -0.020 179.540 39.300 ;
    END
    PORT
      LAYER met4 ;
        RECT 177.940 490.700 179.540 897.620 ;
    END
    PORT
      LAYER met4 ;
        RECT 331.540 -0.020 333.140 39.300 ;
    END
    PORT
      LAYER met4 ;
        RECT 331.540 490.700 333.140 897.620 ;
    END
    PORT
      LAYER met4 ;
        RECT 485.140 -0.020 486.740 897.620 ;
    END
    PORT
      LAYER met4 ;
        RECT 638.740 -0.020 640.340 897.620 ;
    END
    PORT
      LAYER met5 ;
        RECT -5.380 30.030 655.360 31.630 ;
    END
    PORT
      LAYER met5 ;
        RECT -5.380 183.210 655.360 184.810 ;
    END
    PORT
      LAYER met5 ;
        RECT -5.380 336.390 655.360 337.990 ;
    END
    PORT
      LAYER met5 ;
        RECT -5.380 489.570 655.360 491.170 ;
    END
    PORT
      LAYER met5 ;
        RECT -5.380 642.750 655.360 644.350 ;
    END
    PORT
      LAYER met5 ;
        RECT -5.380 795.930 655.360 797.530 ;
    END
  END vssd1
  PIN wb_clk_i
    DIRECTION INPUT ;
    USE SIGNAL ;
    ANTENNAGATEAREA 0.852000 ;
    ANTENNADIFFAREA 0.434700 ;
    PORT
      LAYER met3 ;
        RECT 646.000 65.320 650.000 65.920 ;
    END
  END wb_clk_i
  PIN wb_rst_i
    DIRECTION INPUT ;
    USE SIGNAL ;
    ANTENNAGATEAREA 0.196500 ;
    PORT
      LAYER met3 ;
        RECT 646.000 70.760 650.000 71.360 ;
    END
  END wb_rst_i
  PIN wbs_ack_control_o
    DIRECTION OUTPUT TRISTATE ;
    USE SIGNAL ;
    ANTENNADIFFAREA 0.795200 ;
    PORT
      LAYER met3 ;
        RECT 646.000 76.200 650.000 76.800 ;
    END
  END wbs_ack_control_o
  PIN wbs_ack_imem_o
    DIRECTION OUTPUT TRISTATE ;
    USE SIGNAL ;
    ANTENNADIFFAREA 0.795200 ;
    PORT
      LAYER met3 ;
        RECT 646.000 81.640 650.000 82.240 ;
    END
  END wbs_ack_imem_o
  PIN wbs_adr_i[0]
    DIRECTION INPUT ;
    USE SIGNAL ;
    PORT
      LAYER met3 ;
        RECT 646.000 108.840 650.000 109.440 ;
    END
  END wbs_adr_i[0]
  PIN wbs_adr_i[10]
    DIRECTION INPUT ;
    USE SIGNAL ;
    ANTENNAGATEAREA 0.213000 ;
    PORT
      LAYER met3 ;
        RECT 646.000 348.200 650.000 348.800 ;
    END
  END wbs_adr_i[10]
  PIN wbs_adr_i[11]
    DIRECTION INPUT ;
    USE SIGNAL ;
    ANTENNAGATEAREA 0.213000 ;
    PORT
      LAYER met3 ;
        RECT 646.000 369.960 650.000 370.560 ;
    END
  END wbs_adr_i[11]
  PIN wbs_adr_i[12]
    DIRECTION INPUT ;
    USE SIGNAL ;
    PORT
      LAYER met3 ;
        RECT 646.000 391.720 650.000 392.320 ;
    END
  END wbs_adr_i[12]
  PIN wbs_adr_i[13]
    DIRECTION INPUT ;
    USE SIGNAL ;
    PORT
      LAYER met3 ;
        RECT 646.000 413.480 650.000 414.080 ;
    END
  END wbs_adr_i[13]
  PIN wbs_adr_i[14]
    DIRECTION INPUT ;
    USE SIGNAL ;
    PORT
      LAYER met3 ;
        RECT 646.000 435.240 650.000 435.840 ;
    END
  END wbs_adr_i[14]
  PIN wbs_adr_i[15]
    DIRECTION INPUT ;
    USE SIGNAL ;
    PORT
      LAYER met3 ;
        RECT 646.000 457.000 650.000 457.600 ;
    END
  END wbs_adr_i[15]
  PIN wbs_adr_i[16]
    DIRECTION INPUT ;
    USE SIGNAL ;
    PORT
      LAYER met3 ;
        RECT 646.000 478.760 650.000 479.360 ;
    END
  END wbs_adr_i[16]
  PIN wbs_adr_i[17]
    DIRECTION INPUT ;
    USE SIGNAL ;
    PORT
      LAYER met3 ;
        RECT 646.000 500.520 650.000 501.120 ;
    END
  END wbs_adr_i[17]
  PIN wbs_adr_i[18]
    DIRECTION INPUT ;
    USE SIGNAL ;
    PORT
      LAYER met3 ;
        RECT 646.000 522.280 650.000 522.880 ;
    END
  END wbs_adr_i[18]
  PIN wbs_adr_i[19]
    DIRECTION INPUT ;
    USE SIGNAL ;
    PORT
      LAYER met3 ;
        RECT 646.000 544.040 650.000 544.640 ;
    END
  END wbs_adr_i[19]
  PIN wbs_adr_i[1]
    DIRECTION INPUT ;
    USE SIGNAL ;
    PORT
      LAYER met3 ;
        RECT 646.000 136.040 650.000 136.640 ;
    END
  END wbs_adr_i[1]
  PIN wbs_adr_i[20]
    DIRECTION INPUT ;
    USE SIGNAL ;
    PORT
      LAYER met3 ;
        RECT 646.000 565.800 650.000 566.400 ;
    END
  END wbs_adr_i[20]
  PIN wbs_adr_i[21]
    DIRECTION INPUT ;
    USE SIGNAL ;
    PORT
      LAYER met3 ;
        RECT 646.000 587.560 650.000 588.160 ;
    END
  END wbs_adr_i[21]
  PIN wbs_adr_i[22]
    DIRECTION INPUT ;
    USE SIGNAL ;
    PORT
      LAYER met3 ;
        RECT 646.000 609.320 650.000 609.920 ;
    END
  END wbs_adr_i[22]
  PIN wbs_adr_i[23]
    DIRECTION INPUT ;
    USE SIGNAL ;
    PORT
      LAYER met3 ;
        RECT 646.000 631.080 650.000 631.680 ;
    END
  END wbs_adr_i[23]
  PIN wbs_adr_i[24]
    DIRECTION INPUT ;
    USE SIGNAL ;
    PORT
      LAYER met3 ;
        RECT 646.000 652.840 650.000 653.440 ;
    END
  END wbs_adr_i[24]
  PIN wbs_adr_i[25]
    DIRECTION INPUT ;
    USE SIGNAL ;
    PORT
      LAYER met3 ;
        RECT 646.000 674.600 650.000 675.200 ;
    END
  END wbs_adr_i[25]
  PIN wbs_adr_i[26]
    DIRECTION INPUT ;
    USE SIGNAL ;
    PORT
      LAYER met3 ;
        RECT 646.000 696.360 650.000 696.960 ;
    END
  END wbs_adr_i[26]
  PIN wbs_adr_i[27]
    DIRECTION INPUT ;
    USE SIGNAL ;
    PORT
      LAYER met3 ;
        RECT 646.000 718.120 650.000 718.720 ;
    END
  END wbs_adr_i[27]
  PIN wbs_adr_i[28]
    DIRECTION INPUT ;
    USE SIGNAL ;
    PORT
      LAYER met3 ;
        RECT 646.000 739.880 650.000 740.480 ;
    END
  END wbs_adr_i[28]
  PIN wbs_adr_i[29]
    DIRECTION INPUT ;
    USE SIGNAL ;
    PORT
      LAYER met3 ;
        RECT 646.000 761.640 650.000 762.240 ;
    END
  END wbs_adr_i[29]
  PIN wbs_adr_i[2]
    DIRECTION INPUT ;
    USE SIGNAL ;
    ANTENNAGATEAREA 0.213000 ;
    PORT
      LAYER met3 ;
        RECT 646.000 163.240 650.000 163.840 ;
    END
  END wbs_adr_i[2]
  PIN wbs_adr_i[30]
    DIRECTION INPUT ;
    USE SIGNAL ;
    PORT
      LAYER met3 ;
        RECT 646.000 783.400 650.000 784.000 ;
    END
  END wbs_adr_i[30]
  PIN wbs_adr_i[31]
    DIRECTION INPUT ;
    USE SIGNAL ;
    PORT
      LAYER met3 ;
        RECT 646.000 805.160 650.000 805.760 ;
    END
  END wbs_adr_i[31]
  PIN wbs_adr_i[3]
    DIRECTION INPUT ;
    USE SIGNAL ;
    ANTENNAGATEAREA 0.213000 ;
    PORT
      LAYER met3 ;
        RECT 646.000 190.440 650.000 191.040 ;
    END
  END wbs_adr_i[3]
  PIN wbs_adr_i[4]
    DIRECTION INPUT ;
    USE SIGNAL ;
    ANTENNAGATEAREA 0.213000 ;
    PORT
      LAYER met3 ;
        RECT 646.000 217.640 650.000 218.240 ;
    END
  END wbs_adr_i[4]
  PIN wbs_adr_i[5]
    DIRECTION INPUT ;
    USE SIGNAL ;
    ANTENNAGATEAREA 0.213000 ;
    PORT
      LAYER met3 ;
        RECT 646.000 239.400 650.000 240.000 ;
    END
  END wbs_adr_i[5]
  PIN wbs_adr_i[6]
    DIRECTION INPUT ;
    USE SIGNAL ;
    ANTENNAGATEAREA 0.213000 ;
    PORT
      LAYER met3 ;
        RECT 646.000 261.160 650.000 261.760 ;
    END
  END wbs_adr_i[6]
  PIN wbs_adr_i[7]
    DIRECTION INPUT ;
    USE SIGNAL ;
    ANTENNAGATEAREA 0.426000 ;
    PORT
      LAYER met3 ;
        RECT 646.000 282.920 650.000 283.520 ;
    END
  END wbs_adr_i[7]
  PIN wbs_adr_i[8]
    DIRECTION INPUT ;
    USE SIGNAL ;
    ANTENNAGATEAREA 0.213000 ;
    PORT
      LAYER met3 ;
        RECT 646.000 304.680 650.000 305.280 ;
    END
  END wbs_adr_i[8]
  PIN wbs_adr_i[9]
    DIRECTION INPUT ;
    USE SIGNAL ;
    ANTENNAGATEAREA 0.213000 ;
    PORT
      LAYER met3 ;
        RECT 646.000 326.440 650.000 327.040 ;
    END
  END wbs_adr_i[9]
  PIN wbs_cyc_i
    DIRECTION INPUT ;
    USE SIGNAL ;
    ANTENNAGATEAREA 0.126000 ;
    PORT
      LAYER met3 ;
        RECT 646.000 87.080 650.000 87.680 ;
    END
  END wbs_cyc_i
  PIN wbs_dat_control_o[0]
    DIRECTION OUTPUT TRISTATE ;
    USE SIGNAL ;
    ANTENNADIFFAREA 0.445500 ;
    PORT
      LAYER met3 ;
        RECT 646.000 114.280 650.000 114.880 ;
    END
  END wbs_dat_control_o[0]
  PIN wbs_dat_control_o[10]
    DIRECTION OUTPUT TRISTATE ;
    USE SIGNAL ;
    ANTENNADIFFAREA 0.445500 ;
    PORT
      LAYER met3 ;
        RECT 646.000 353.640 650.000 354.240 ;
    END
  END wbs_dat_control_o[10]
  PIN wbs_dat_control_o[11]
    DIRECTION OUTPUT TRISTATE ;
    USE SIGNAL ;
    ANTENNADIFFAREA 0.445500 ;
    PORT
      LAYER met3 ;
        RECT 646.000 375.400 650.000 376.000 ;
    END
  END wbs_dat_control_o[11]
  PIN wbs_dat_control_o[12]
    DIRECTION OUTPUT TRISTATE ;
    USE SIGNAL ;
    ANTENNADIFFAREA 0.795200 ;
    PORT
      LAYER met3 ;
        RECT 646.000 397.160 650.000 397.760 ;
    END
  END wbs_dat_control_o[12]
  PIN wbs_dat_control_o[13]
    DIRECTION OUTPUT TRISTATE ;
    USE SIGNAL ;
    ANTENNADIFFAREA 0.795200 ;
    PORT
      LAYER met3 ;
        RECT 646.000 418.920 650.000 419.520 ;
    END
  END wbs_dat_control_o[13]
  PIN wbs_dat_control_o[14]
    DIRECTION OUTPUT TRISTATE ;
    USE SIGNAL ;
    ANTENNADIFFAREA 0.795200 ;
    PORT
      LAYER met3 ;
        RECT 646.000 440.680 650.000 441.280 ;
    END
  END wbs_dat_control_o[14]
  PIN wbs_dat_control_o[15]
    DIRECTION OUTPUT TRISTATE ;
    USE SIGNAL ;
    ANTENNADIFFAREA 0.795200 ;
    PORT
      LAYER met3 ;
        RECT 646.000 462.440 650.000 463.040 ;
    END
  END wbs_dat_control_o[15]
  PIN wbs_dat_control_o[16]
    DIRECTION OUTPUT TRISTATE ;
    USE SIGNAL ;
    ANTENNADIFFAREA 0.445500 ;
    PORT
      LAYER met3 ;
        RECT 646.000 484.200 650.000 484.800 ;
    END
  END wbs_dat_control_o[16]
  PIN wbs_dat_control_o[17]
    DIRECTION OUTPUT TRISTATE ;
    USE SIGNAL ;
    ANTENNADIFFAREA 0.445500 ;
    PORT
      LAYER met3 ;
        RECT 646.000 505.960 650.000 506.560 ;
    END
  END wbs_dat_control_o[17]
  PIN wbs_dat_control_o[18]
    DIRECTION OUTPUT TRISTATE ;
    USE SIGNAL ;
    ANTENNADIFFAREA 0.795200 ;
    PORT
      LAYER met3 ;
        RECT 646.000 527.720 650.000 528.320 ;
    END
  END wbs_dat_control_o[18]
  PIN wbs_dat_control_o[19]
    DIRECTION OUTPUT TRISTATE ;
    USE SIGNAL ;
    ANTENNADIFFAREA 0.445500 ;
    PORT
      LAYER met3 ;
        RECT 646.000 549.480 650.000 550.080 ;
    END
  END wbs_dat_control_o[19]
  PIN wbs_dat_control_o[1]
    DIRECTION OUTPUT TRISTATE ;
    USE SIGNAL ;
    ANTENNADIFFAREA 0.795200 ;
    PORT
      LAYER met3 ;
        RECT 646.000 141.480 650.000 142.080 ;
    END
  END wbs_dat_control_o[1]
  PIN wbs_dat_control_o[20]
    DIRECTION OUTPUT TRISTATE ;
    USE SIGNAL ;
    ANTENNADIFFAREA 0.445500 ;
    PORT
      LAYER met3 ;
        RECT 646.000 571.240 650.000 571.840 ;
    END
  END wbs_dat_control_o[20]
  PIN wbs_dat_control_o[21]
    DIRECTION OUTPUT TRISTATE ;
    USE SIGNAL ;
    ANTENNADIFFAREA 0.795200 ;
    PORT
      LAYER met3 ;
        RECT 646.000 593.000 650.000 593.600 ;
    END
  END wbs_dat_control_o[21]
  PIN wbs_dat_control_o[22]
    DIRECTION OUTPUT TRISTATE ;
    USE SIGNAL ;
    ANTENNADIFFAREA 0.445500 ;
    PORT
      LAYER met3 ;
        RECT 646.000 614.760 650.000 615.360 ;
    END
  END wbs_dat_control_o[22]
  PIN wbs_dat_control_o[23]
    DIRECTION OUTPUT TRISTATE ;
    USE SIGNAL ;
    ANTENNADIFFAREA 0.445500 ;
    PORT
      LAYER met3 ;
        RECT 646.000 636.520 650.000 637.120 ;
    END
  END wbs_dat_control_o[23]
  PIN wbs_dat_control_o[24]
    DIRECTION OUTPUT TRISTATE ;
    USE SIGNAL ;
    ANTENNADIFFAREA 0.445500 ;
    PORT
      LAYER met3 ;
        RECT 646.000 658.280 650.000 658.880 ;
    END
  END wbs_dat_control_o[24]
  PIN wbs_dat_control_o[25]
    DIRECTION OUTPUT TRISTATE ;
    USE SIGNAL ;
    ANTENNADIFFAREA 0.445500 ;
    PORT
      LAYER met3 ;
        RECT 646.000 680.040 650.000 680.640 ;
    END
  END wbs_dat_control_o[25]
  PIN wbs_dat_control_o[26]
    DIRECTION OUTPUT TRISTATE ;
    USE SIGNAL ;
    ANTENNADIFFAREA 0.445500 ;
    PORT
      LAYER met3 ;
        RECT 646.000 701.800 650.000 702.400 ;
    END
  END wbs_dat_control_o[26]
  PIN wbs_dat_control_o[27]
    DIRECTION OUTPUT TRISTATE ;
    USE SIGNAL ;
    ANTENNADIFFAREA 0.795200 ;
    PORT
      LAYER met3 ;
        RECT 646.000 723.560 650.000 724.160 ;
    END
  END wbs_dat_control_o[27]
  PIN wbs_dat_control_o[28]
    DIRECTION OUTPUT TRISTATE ;
    USE SIGNAL ;
    ANTENNADIFFAREA 0.445500 ;
    PORT
      LAYER met3 ;
        RECT 646.000 745.320 650.000 745.920 ;
    END
  END wbs_dat_control_o[28]
  PIN wbs_dat_control_o[29]
    DIRECTION OUTPUT TRISTATE ;
    USE SIGNAL ;
    ANTENNADIFFAREA 0.445500 ;
    PORT
      LAYER met3 ;
        RECT 646.000 767.080 650.000 767.680 ;
    END
  END wbs_dat_control_o[29]
  PIN wbs_dat_control_o[2]
    DIRECTION OUTPUT TRISTATE ;
    USE SIGNAL ;
    ANTENNADIFFAREA 0.795200 ;
    PORT
      LAYER met3 ;
        RECT 646.000 168.680 650.000 169.280 ;
    END
  END wbs_dat_control_o[2]
  PIN wbs_dat_control_o[30]
    DIRECTION OUTPUT TRISTATE ;
    USE SIGNAL ;
    ANTENNADIFFAREA 0.445500 ;
    PORT
      LAYER met3 ;
        RECT 646.000 788.840 650.000 789.440 ;
    END
  END wbs_dat_control_o[30]
  PIN wbs_dat_control_o[31]
    DIRECTION OUTPUT TRISTATE ;
    USE SIGNAL ;
    ANTENNADIFFAREA 0.445500 ;
    PORT
      LAYER met3 ;
        RECT 646.000 810.600 650.000 811.200 ;
    END
  END wbs_dat_control_o[31]
  PIN wbs_dat_control_o[3]
    DIRECTION OUTPUT TRISTATE ;
    USE SIGNAL ;
    ANTENNADIFFAREA 0.445500 ;
    PORT
      LAYER met3 ;
        RECT 646.000 195.880 650.000 196.480 ;
    END
  END wbs_dat_control_o[3]
  PIN wbs_dat_control_o[4]
    DIRECTION OUTPUT TRISTATE ;
    USE SIGNAL ;
    ANTENNADIFFAREA 0.445500 ;
    PORT
      LAYER met3 ;
        RECT 646.000 223.080 650.000 223.680 ;
    END
  END wbs_dat_control_o[4]
  PIN wbs_dat_control_o[5]
    DIRECTION OUTPUT TRISTATE ;
    USE SIGNAL ;
    ANTENNADIFFAREA 0.445500 ;
    PORT
      LAYER met3 ;
        RECT 646.000 244.840 650.000 245.440 ;
    END
  END wbs_dat_control_o[5]
  PIN wbs_dat_control_o[6]
    DIRECTION OUTPUT TRISTATE ;
    USE SIGNAL ;
    ANTENNADIFFAREA 0.445500 ;
    PORT
      LAYER met3 ;
        RECT 646.000 266.600 650.000 267.200 ;
    END
  END wbs_dat_control_o[6]
  PIN wbs_dat_control_o[7]
    DIRECTION OUTPUT TRISTATE ;
    USE SIGNAL ;
    ANTENNADIFFAREA 0.795200 ;
    PORT
      LAYER met3 ;
        RECT 646.000 288.360 650.000 288.960 ;
    END
  END wbs_dat_control_o[7]
  PIN wbs_dat_control_o[8]
    DIRECTION OUTPUT TRISTATE ;
    USE SIGNAL ;
    ANTENNADIFFAREA 0.795200 ;
    PORT
      LAYER met3 ;
        RECT 646.000 310.120 650.000 310.720 ;
    END
  END wbs_dat_control_o[8]
  PIN wbs_dat_control_o[9]
    DIRECTION OUTPUT TRISTATE ;
    USE SIGNAL ;
    ANTENNADIFFAREA 0.795200 ;
    PORT
      LAYER met3 ;
        RECT 646.000 331.880 650.000 332.480 ;
    END
  END wbs_dat_control_o[9]
  PIN wbs_dat_i[0]
    DIRECTION INPUT ;
    USE SIGNAL ;
    ANTENNAGATEAREA 0.742500 ;
    PORT
      LAYER met3 ;
        RECT 646.000 119.720 650.000 120.320 ;
    END
  END wbs_dat_i[0]
  PIN wbs_dat_i[10]
    DIRECTION INPUT ;
    USE SIGNAL ;
    ANTENNAGATEAREA 0.742500 ;
    PORT
      LAYER met3 ;
        RECT 646.000 359.080 650.000 359.680 ;
    END
  END wbs_dat_i[10]
  PIN wbs_dat_i[11]
    DIRECTION INPUT ;
    USE SIGNAL ;
    ANTENNAGATEAREA 0.742500 ;
    PORT
      LAYER met3 ;
        RECT 646.000 380.840 650.000 381.440 ;
    END
  END wbs_dat_i[11]
  PIN wbs_dat_i[12]
    DIRECTION INPUT ;
    USE SIGNAL ;
    ANTENNAGATEAREA 0.247500 ;
    PORT
      LAYER met3 ;
        RECT 646.000 402.600 650.000 403.200 ;
    END
  END wbs_dat_i[12]
  PIN wbs_dat_i[13]
    DIRECTION INPUT ;
    USE SIGNAL ;
    ANTENNAGATEAREA 0.247500 ;
    PORT
      LAYER met3 ;
        RECT 646.000 424.360 650.000 424.960 ;
    END
  END wbs_dat_i[13]
  PIN wbs_dat_i[14]
    DIRECTION INPUT ;
    USE SIGNAL ;
    ANTENNAGATEAREA 0.247500 ;
    PORT
      LAYER met3 ;
        RECT 646.000 446.120 650.000 446.720 ;
    END
  END wbs_dat_i[14]
  PIN wbs_dat_i[15]
    DIRECTION INPUT ;
    USE SIGNAL ;
    ANTENNAGATEAREA 0.247500 ;
    PORT
      LAYER met3 ;
        RECT 646.000 467.880 650.000 468.480 ;
    END
  END wbs_dat_i[15]
  PIN wbs_dat_i[16]
    DIRECTION INPUT ;
    USE SIGNAL ;
    ANTENNAGATEAREA 0.426000 ;
    PORT
      LAYER met3 ;
        RECT 646.000 489.640 650.000 490.240 ;
    END
  END wbs_dat_i[16]
  PIN wbs_dat_i[17]
    DIRECTION INPUT ;
    USE SIGNAL ;
    ANTENNAGATEAREA 0.742500 ;
    PORT
      LAYER met3 ;
        RECT 646.000 511.400 650.000 512.000 ;
    END
  END wbs_dat_i[17]
  PIN wbs_dat_i[18]
    DIRECTION INPUT ;
    USE SIGNAL ;
    ANTENNAGATEAREA 0.495000 ;
    PORT
      LAYER met3 ;
        RECT 646.000 533.160 650.000 533.760 ;
    END
  END wbs_dat_i[18]
  PIN wbs_dat_i[19]
    DIRECTION INPUT ;
    USE SIGNAL ;
    ANTENNAGATEAREA 0.426000 ;
    PORT
      LAYER met3 ;
        RECT 646.000 554.920 650.000 555.520 ;
    END
  END wbs_dat_i[19]
  PIN wbs_dat_i[1]
    DIRECTION INPUT ;
    USE SIGNAL ;
    ANTENNAGATEAREA 0.742500 ;
    PORT
      LAYER met3 ;
        RECT 646.000 146.920 650.000 147.520 ;
    END
  END wbs_dat_i[1]
  PIN wbs_dat_i[20]
    DIRECTION INPUT ;
    USE SIGNAL ;
    ANTENNAGATEAREA 0.495000 ;
    PORT
      LAYER met3 ;
        RECT 646.000 576.680 650.000 577.280 ;
    END
  END wbs_dat_i[20]
  PIN wbs_dat_i[21]
    DIRECTION INPUT ;
    USE SIGNAL ;
    ANTENNAGATEAREA 0.742500 ;
    PORT
      LAYER met3 ;
        RECT 646.000 598.440 650.000 599.040 ;
    END
  END wbs_dat_i[21]
  PIN wbs_dat_i[22]
    DIRECTION INPUT ;
    USE SIGNAL ;
    ANTENNAGATEAREA 0.742500 ;
    PORT
      LAYER met3 ;
        RECT 646.000 620.200 650.000 620.800 ;
    END
  END wbs_dat_i[22]
  PIN wbs_dat_i[23]
    DIRECTION INPUT ;
    USE SIGNAL ;
    ANTENNAGATEAREA 0.426000 ;
    PORT
      LAYER met3 ;
        RECT 646.000 641.960 650.000 642.560 ;
    END
  END wbs_dat_i[23]
  PIN wbs_dat_i[24]
    DIRECTION INPUT ;
    USE SIGNAL ;
    ANTENNAGATEAREA 0.495000 ;
    PORT
      LAYER met3 ;
        RECT 646.000 663.720 650.000 664.320 ;
    END
  END wbs_dat_i[24]
  PIN wbs_dat_i[25]
    DIRECTION INPUT ;
    USE SIGNAL ;
    ANTENNAGATEAREA 0.742500 ;
    PORT
      LAYER met3 ;
        RECT 646.000 685.480 650.000 686.080 ;
    END
  END wbs_dat_i[25]
  PIN wbs_dat_i[26]
    DIRECTION INPUT ;
    USE SIGNAL ;
    ANTENNAGATEAREA 0.742500 ;
    PORT
      LAYER met3 ;
        RECT 646.000 707.240 650.000 707.840 ;
    END
  END wbs_dat_i[26]
  PIN wbs_dat_i[27]
    DIRECTION INPUT ;
    USE SIGNAL ;
    ANTENNAGATEAREA 0.742500 ;
    PORT
      LAYER met3 ;
        RECT 646.000 729.000 650.000 729.600 ;
    END
  END wbs_dat_i[27]
  PIN wbs_dat_i[28]
    DIRECTION INPUT ;
    USE SIGNAL ;
    ANTENNAGATEAREA 0.742500 ;
    PORT
      LAYER met3 ;
        RECT 646.000 750.760 650.000 751.360 ;
    END
  END wbs_dat_i[28]
  PIN wbs_dat_i[29]
    DIRECTION INPUT ;
    USE SIGNAL ;
    ANTENNAGATEAREA 0.742500 ;
    PORT
      LAYER met3 ;
        RECT 646.000 772.520 650.000 773.120 ;
    END
  END wbs_dat_i[29]
  PIN wbs_dat_i[2]
    DIRECTION INPUT ;
    USE SIGNAL ;
    ANTENNAGATEAREA 0.742500 ;
    PORT
      LAYER met3 ;
        RECT 646.000 174.120 650.000 174.720 ;
    END
  END wbs_dat_i[2]
  PIN wbs_dat_i[30]
    DIRECTION INPUT ;
    USE SIGNAL ;
    ANTENNAGATEAREA 0.495000 ;
    PORT
      LAYER met3 ;
        RECT 646.000 794.280 650.000 794.880 ;
    END
  END wbs_dat_i[30]
  PIN wbs_dat_i[31]
    DIRECTION INPUT ;
    USE SIGNAL ;
    ANTENNAGATEAREA 0.742500 ;
    PORT
      LAYER met3 ;
        RECT 646.000 816.040 650.000 816.640 ;
    END
  END wbs_dat_i[31]
  PIN wbs_dat_i[3]
    DIRECTION INPUT ;
    USE SIGNAL ;
    ANTENNAGATEAREA 0.742500 ;
    PORT
      LAYER met3 ;
        RECT 646.000 201.320 650.000 201.920 ;
    END
  END wbs_dat_i[3]
  PIN wbs_dat_i[4]
    DIRECTION INPUT ;
    USE SIGNAL ;
    ANTENNAGATEAREA 0.426000 ;
    PORT
      LAYER met3 ;
        RECT 646.000 228.520 650.000 229.120 ;
    END
  END wbs_dat_i[4]
  PIN wbs_dat_i[5]
    DIRECTION INPUT ;
    USE SIGNAL ;
    ANTENNAGATEAREA 0.426000 ;
    PORT
      LAYER met3 ;
        RECT 646.000 250.280 650.000 250.880 ;
    END
  END wbs_dat_i[5]
  PIN wbs_dat_i[6]
    DIRECTION INPUT ;
    USE SIGNAL ;
    ANTENNAGATEAREA 0.426000 ;
    PORT
      LAYER met3 ;
        RECT 646.000 272.040 650.000 272.640 ;
    END
  END wbs_dat_i[6]
  PIN wbs_dat_i[7]
    DIRECTION INPUT ;
    USE SIGNAL ;
    ANTENNAGATEAREA 0.495000 ;
    PORT
      LAYER met3 ;
        RECT 646.000 293.800 650.000 294.400 ;
    END
  END wbs_dat_i[7]
  PIN wbs_dat_i[8]
    DIRECTION INPUT ;
    USE SIGNAL ;
    ANTENNAGATEAREA 0.742500 ;
    PORT
      LAYER met3 ;
        RECT 646.000 315.560 650.000 316.160 ;
    END
  END wbs_dat_i[8]
  PIN wbs_dat_i[9]
    DIRECTION INPUT ;
    USE SIGNAL ;
    ANTENNAGATEAREA 0.742500 ;
    PORT
      LAYER met3 ;
        RECT 646.000 337.320 650.000 337.920 ;
    END
  END wbs_dat_i[9]
  PIN wbs_dat_imem_o[0]
    DIRECTION OUTPUT TRISTATE ;
    USE SIGNAL ;
    ANTENNADIFFAREA 0.795200 ;
    PORT
      LAYER met3 ;
        RECT 646.000 125.160 650.000 125.760 ;
    END
  END wbs_dat_imem_o[0]
  PIN wbs_dat_imem_o[10]
    DIRECTION OUTPUT TRISTATE ;
    USE SIGNAL ;
    ANTENNADIFFAREA 0.445500 ;
    PORT
      LAYER met3 ;
        RECT 646.000 364.520 650.000 365.120 ;
    END
  END wbs_dat_imem_o[10]
  PIN wbs_dat_imem_o[11]
    DIRECTION OUTPUT TRISTATE ;
    USE SIGNAL ;
    ANTENNADIFFAREA 0.445500 ;
    PORT
      LAYER met3 ;
        RECT 646.000 386.280 650.000 386.880 ;
    END
  END wbs_dat_imem_o[11]
  PIN wbs_dat_imem_o[12]
    DIRECTION OUTPUT TRISTATE ;
    USE SIGNAL ;
    ANTENNADIFFAREA 0.795200 ;
    PORT
      LAYER met3 ;
        RECT 646.000 408.040 650.000 408.640 ;
    END
  END wbs_dat_imem_o[12]
  PIN wbs_dat_imem_o[13]
    DIRECTION OUTPUT TRISTATE ;
    USE SIGNAL ;
    ANTENNADIFFAREA 0.795200 ;
    PORT
      LAYER met3 ;
        RECT 646.000 429.800 650.000 430.400 ;
    END
  END wbs_dat_imem_o[13]
  PIN wbs_dat_imem_o[14]
    DIRECTION OUTPUT TRISTATE ;
    USE SIGNAL ;
    ANTENNADIFFAREA 0.795200 ;
    PORT
      LAYER met3 ;
        RECT 646.000 451.560 650.000 452.160 ;
    END
  END wbs_dat_imem_o[14]
  PIN wbs_dat_imem_o[15]
    DIRECTION OUTPUT TRISTATE ;
    USE SIGNAL ;
    ANTENNADIFFAREA 0.445500 ;
    PORT
      LAYER met3 ;
        RECT 646.000 473.320 650.000 473.920 ;
    END
  END wbs_dat_imem_o[15]
  PIN wbs_dat_imem_o[16]
    DIRECTION OUTPUT TRISTATE ;
    USE SIGNAL ;
    ANTENNADIFFAREA 0.445500 ;
    PORT
      LAYER met3 ;
        RECT 646.000 495.080 650.000 495.680 ;
    END
  END wbs_dat_imem_o[16]
  PIN wbs_dat_imem_o[17]
    DIRECTION OUTPUT TRISTATE ;
    USE SIGNAL ;
    ANTENNADIFFAREA 0.795200 ;
    PORT
      LAYER met3 ;
        RECT 646.000 516.840 650.000 517.440 ;
    END
  END wbs_dat_imem_o[17]
  PIN wbs_dat_imem_o[18]
    DIRECTION OUTPUT TRISTATE ;
    USE SIGNAL ;
    ANTENNADIFFAREA 0.795200 ;
    PORT
      LAYER met3 ;
        RECT 646.000 538.600 650.000 539.200 ;
    END
  END wbs_dat_imem_o[18]
  PIN wbs_dat_imem_o[19]
    DIRECTION OUTPUT TRISTATE ;
    USE SIGNAL ;
    ANTENNADIFFAREA 0.445500 ;
    PORT
      LAYER met3 ;
        RECT 646.000 560.360 650.000 560.960 ;
    END
  END wbs_dat_imem_o[19]
  PIN wbs_dat_imem_o[1]
    DIRECTION OUTPUT TRISTATE ;
    USE SIGNAL ;
    ANTENNADIFFAREA 0.795200 ;
    PORT
      LAYER met3 ;
        RECT 646.000 152.360 650.000 152.960 ;
    END
  END wbs_dat_imem_o[1]
  PIN wbs_dat_imem_o[20]
    DIRECTION OUTPUT TRISTATE ;
    USE SIGNAL ;
    ANTENNADIFFAREA 0.445500 ;
    PORT
      LAYER met3 ;
        RECT 646.000 582.120 650.000 582.720 ;
    END
  END wbs_dat_imem_o[20]
  PIN wbs_dat_imem_o[21]
    DIRECTION OUTPUT TRISTATE ;
    USE SIGNAL ;
    ANTENNADIFFAREA 0.795200 ;
    PORT
      LAYER met3 ;
        RECT 646.000 603.880 650.000 604.480 ;
    END
  END wbs_dat_imem_o[21]
  PIN wbs_dat_imem_o[22]
    DIRECTION OUTPUT TRISTATE ;
    USE SIGNAL ;
    ANTENNADIFFAREA 0.445500 ;
    PORT
      LAYER met3 ;
        RECT 646.000 625.640 650.000 626.240 ;
    END
  END wbs_dat_imem_o[22]
  PIN wbs_dat_imem_o[23]
    DIRECTION OUTPUT TRISTATE ;
    USE SIGNAL ;
    ANTENNADIFFAREA 0.795200 ;
    PORT
      LAYER met3 ;
        RECT 646.000 647.400 650.000 648.000 ;
    END
  END wbs_dat_imem_o[23]
  PIN wbs_dat_imem_o[24]
    DIRECTION OUTPUT TRISTATE ;
    USE SIGNAL ;
    ANTENNADIFFAREA 0.445500 ;
    PORT
      LAYER met3 ;
        RECT 646.000 669.160 650.000 669.760 ;
    END
  END wbs_dat_imem_o[24]
  PIN wbs_dat_imem_o[25]
    DIRECTION OUTPUT TRISTATE ;
    USE SIGNAL ;
    ANTENNADIFFAREA 0.445500 ;
    PORT
      LAYER met3 ;
        RECT 646.000 690.920 650.000 691.520 ;
    END
  END wbs_dat_imem_o[25]
  PIN wbs_dat_imem_o[26]
    DIRECTION OUTPUT TRISTATE ;
    USE SIGNAL ;
    ANTENNADIFFAREA 0.445500 ;
    PORT
      LAYER met3 ;
        RECT 646.000 712.680 650.000 713.280 ;
    END
  END wbs_dat_imem_o[26]
  PIN wbs_dat_imem_o[27]
    DIRECTION OUTPUT TRISTATE ;
    USE SIGNAL ;
    ANTENNADIFFAREA 0.445500 ;
    PORT
      LAYER met3 ;
        RECT 646.000 734.440 650.000 735.040 ;
    END
  END wbs_dat_imem_o[27]
  PIN wbs_dat_imem_o[28]
    DIRECTION OUTPUT TRISTATE ;
    USE SIGNAL ;
    ANTENNADIFFAREA 0.795200 ;
    PORT
      LAYER met3 ;
        RECT 646.000 756.200 650.000 756.800 ;
    END
  END wbs_dat_imem_o[28]
  PIN wbs_dat_imem_o[29]
    DIRECTION OUTPUT TRISTATE ;
    USE SIGNAL ;
    ANTENNADIFFAREA 0.795200 ;
    PORT
      LAYER met3 ;
        RECT 646.000 777.960 650.000 778.560 ;
    END
  END wbs_dat_imem_o[29]
  PIN wbs_dat_imem_o[2]
    DIRECTION OUTPUT TRISTATE ;
    USE SIGNAL ;
    ANTENNADIFFAREA 0.795200 ;
    PORT
      LAYER met3 ;
        RECT 646.000 179.560 650.000 180.160 ;
    END
  END wbs_dat_imem_o[2]
  PIN wbs_dat_imem_o[30]
    DIRECTION OUTPUT TRISTATE ;
    USE SIGNAL ;
    ANTENNADIFFAREA 0.795200 ;
    PORT
      LAYER met3 ;
        RECT 646.000 799.720 650.000 800.320 ;
    END
  END wbs_dat_imem_o[30]
  PIN wbs_dat_imem_o[31]
    DIRECTION OUTPUT TRISTATE ;
    USE SIGNAL ;
    ANTENNADIFFAREA 0.795200 ;
    PORT
      LAYER met3 ;
        RECT 646.000 821.480 650.000 822.080 ;
    END
  END wbs_dat_imem_o[31]
  PIN wbs_dat_imem_o[3]
    DIRECTION OUTPUT TRISTATE ;
    USE SIGNAL ;
    ANTENNADIFFAREA 0.445500 ;
    PORT
      LAYER met3 ;
        RECT 646.000 206.760 650.000 207.360 ;
    END
  END wbs_dat_imem_o[3]
  PIN wbs_dat_imem_o[4]
    DIRECTION OUTPUT TRISTATE ;
    USE SIGNAL ;
    ANTENNADIFFAREA 0.795200 ;
    PORT
      LAYER met3 ;
        RECT 646.000 233.960 650.000 234.560 ;
    END
  END wbs_dat_imem_o[4]
  PIN wbs_dat_imem_o[5]
    DIRECTION OUTPUT TRISTATE ;
    USE SIGNAL ;
    ANTENNADIFFAREA 0.445500 ;
    PORT
      LAYER met3 ;
        RECT 646.000 255.720 650.000 256.320 ;
    END
  END wbs_dat_imem_o[5]
  PIN wbs_dat_imem_o[6]
    DIRECTION OUTPUT TRISTATE ;
    USE SIGNAL ;
    ANTENNADIFFAREA 0.795200 ;
    PORT
      LAYER met3 ;
        RECT 646.000 277.480 650.000 278.080 ;
    END
  END wbs_dat_imem_o[6]
  PIN wbs_dat_imem_o[7]
    DIRECTION OUTPUT TRISTATE ;
    USE SIGNAL ;
    ANTENNADIFFAREA 0.795200 ;
    PORT
      LAYER met3 ;
        RECT 646.000 299.240 650.000 299.840 ;
    END
  END wbs_dat_imem_o[7]
  PIN wbs_dat_imem_o[8]
    DIRECTION OUTPUT TRISTATE ;
    USE SIGNAL ;
    ANTENNADIFFAREA 0.795200 ;
    PORT
      LAYER met3 ;
        RECT 646.000 321.000 650.000 321.600 ;
    END
  END wbs_dat_imem_o[8]
  PIN wbs_dat_imem_o[9]
    DIRECTION OUTPUT TRISTATE ;
    USE SIGNAL ;
    ANTENNADIFFAREA 0.795200 ;
    PORT
      LAYER met3 ;
        RECT 646.000 342.760 650.000 343.360 ;
    END
  END wbs_dat_imem_o[9]
  PIN wbs_sel_i[0]
    DIRECTION INPUT ;
    USE SIGNAL ;
    PORT
      LAYER met3 ;
        RECT 646.000 130.600 650.000 131.200 ;
    END
  END wbs_sel_i[0]
  PIN wbs_sel_i[1]
    DIRECTION INPUT ;
    USE SIGNAL ;
    PORT
      LAYER met3 ;
        RECT 646.000 157.800 650.000 158.400 ;
    END
  END wbs_sel_i[1]
  PIN wbs_sel_i[2]
    DIRECTION INPUT ;
    USE SIGNAL ;
    PORT
      LAYER met3 ;
        RECT 646.000 185.000 650.000 185.600 ;
    END
  END wbs_sel_i[2]
  PIN wbs_sel_i[3]
    DIRECTION INPUT ;
    USE SIGNAL ;
    PORT
      LAYER met3 ;
        RECT 646.000 212.200 650.000 212.800 ;
    END
  END wbs_sel_i[3]
  PIN wbs_stb_control_i
    DIRECTION INPUT ;
    USE SIGNAL ;
    ANTENNAGATEAREA 0.159000 ;
    PORT
      LAYER met3 ;
        RECT 646.000 92.520 650.000 93.120 ;
    END
  END wbs_stb_control_i
  PIN wbs_stb_imem_i
    DIRECTION INPUT ;
    USE SIGNAL ;
    ANTENNAGATEAREA 0.213000 ;
    PORT
      LAYER met3 ;
        RECT 646.000 97.960 650.000 98.560 ;
    END
  END wbs_stb_imem_i
  PIN wbs_we_i
    DIRECTION INPUT ;
    USE SIGNAL ;
    ANTENNAGATEAREA 0.159000 ;
    PORT
      LAYER met3 ;
        RECT 646.000 103.400 650.000 104.000 ;
    END
  END wbs_we_i
  OBS
      LAYER li1 ;
        RECT 5.520 10.795 644.460 886.805 ;
      LAYER met1 ;
        RECT 0.070 10.640 645.310 890.080 ;
      LAYER met2 ;
        RECT 0.100 895.720 7.630 896.650 ;
        RECT 8.470 895.720 13.610 896.650 ;
        RECT 14.450 895.720 19.590 896.650 ;
        RECT 20.430 895.720 25.570 896.650 ;
        RECT 26.410 895.720 31.550 896.650 ;
        RECT 32.390 895.720 37.530 896.650 ;
        RECT 38.370 895.720 43.510 896.650 ;
        RECT 44.350 895.720 49.490 896.650 ;
        RECT 50.330 895.720 55.470 896.650 ;
        RECT 56.310 895.720 61.450 896.650 ;
        RECT 62.290 895.720 67.430 896.650 ;
        RECT 68.270 895.720 73.410 896.650 ;
        RECT 74.250 895.720 79.390 896.650 ;
        RECT 80.230 895.720 85.370 896.650 ;
        RECT 86.210 895.720 91.350 896.650 ;
        RECT 92.190 895.720 97.330 896.650 ;
        RECT 98.170 895.720 103.310 896.650 ;
        RECT 104.150 895.720 109.290 896.650 ;
        RECT 110.130 895.720 115.270 896.650 ;
        RECT 116.110 895.720 121.250 896.650 ;
        RECT 122.090 895.720 127.230 896.650 ;
        RECT 128.070 895.720 133.210 896.650 ;
        RECT 134.050 895.720 139.190 896.650 ;
        RECT 140.030 895.720 145.170 896.650 ;
        RECT 146.010 895.720 151.150 896.650 ;
        RECT 151.990 895.720 157.130 896.650 ;
        RECT 157.970 895.720 163.110 896.650 ;
        RECT 163.950 895.720 169.090 896.650 ;
        RECT 169.930 895.720 175.070 896.650 ;
        RECT 175.910 895.720 181.050 896.650 ;
        RECT 181.890 895.720 187.030 896.650 ;
        RECT 187.870 895.720 193.010 896.650 ;
        RECT 193.850 895.720 198.990 896.650 ;
        RECT 199.830 895.720 204.970 896.650 ;
        RECT 205.810 895.720 210.950 896.650 ;
        RECT 211.790 895.720 216.930 896.650 ;
        RECT 217.770 895.720 222.910 896.650 ;
        RECT 223.750 895.720 228.890 896.650 ;
        RECT 229.730 895.720 234.870 896.650 ;
        RECT 235.710 895.720 240.850 896.650 ;
        RECT 241.690 895.720 246.830 896.650 ;
        RECT 247.670 895.720 252.810 896.650 ;
        RECT 253.650 895.720 258.790 896.650 ;
        RECT 259.630 895.720 264.770 896.650 ;
        RECT 265.610 895.720 270.750 896.650 ;
        RECT 271.590 895.720 276.730 896.650 ;
        RECT 277.570 895.720 282.710 896.650 ;
        RECT 283.550 895.720 288.690 896.650 ;
        RECT 289.530 895.720 294.670 896.650 ;
        RECT 295.510 895.720 300.650 896.650 ;
        RECT 301.490 895.720 306.630 896.650 ;
        RECT 307.470 895.720 312.610 896.650 ;
        RECT 313.450 895.720 318.590 896.650 ;
        RECT 319.430 895.720 324.570 896.650 ;
        RECT 325.410 895.720 330.550 896.650 ;
        RECT 331.390 895.720 336.530 896.650 ;
        RECT 337.370 895.720 342.510 896.650 ;
        RECT 343.350 895.720 348.490 896.650 ;
        RECT 349.330 895.720 354.470 896.650 ;
        RECT 355.310 895.720 360.450 896.650 ;
        RECT 361.290 895.720 366.430 896.650 ;
        RECT 367.270 895.720 372.410 896.650 ;
        RECT 373.250 895.720 378.390 896.650 ;
        RECT 379.230 895.720 384.370 896.650 ;
        RECT 385.210 895.720 390.350 896.650 ;
        RECT 391.190 895.720 396.330 896.650 ;
        RECT 397.170 895.720 402.310 896.650 ;
        RECT 403.150 895.720 408.290 896.650 ;
        RECT 409.130 895.720 414.270 896.650 ;
        RECT 415.110 895.720 420.250 896.650 ;
        RECT 421.090 895.720 426.230 896.650 ;
        RECT 427.070 895.720 432.210 896.650 ;
        RECT 433.050 895.720 438.190 896.650 ;
        RECT 439.030 895.720 444.170 896.650 ;
        RECT 445.010 895.720 450.150 896.650 ;
        RECT 450.990 895.720 456.130 896.650 ;
        RECT 456.970 895.720 462.110 896.650 ;
        RECT 462.950 895.720 468.090 896.650 ;
        RECT 468.930 895.720 474.070 896.650 ;
        RECT 474.910 895.720 480.050 896.650 ;
        RECT 480.890 895.720 486.030 896.650 ;
        RECT 486.870 895.720 492.010 896.650 ;
        RECT 492.850 895.720 497.990 896.650 ;
        RECT 498.830 895.720 503.970 896.650 ;
        RECT 504.810 895.720 509.950 896.650 ;
        RECT 510.790 895.720 515.930 896.650 ;
        RECT 516.770 895.720 521.910 896.650 ;
        RECT 522.750 895.720 527.890 896.650 ;
        RECT 528.730 895.720 533.870 896.650 ;
        RECT 534.710 895.720 539.850 896.650 ;
        RECT 540.690 895.720 545.830 896.650 ;
        RECT 546.670 895.720 551.810 896.650 ;
        RECT 552.650 895.720 557.790 896.650 ;
        RECT 558.630 895.720 563.770 896.650 ;
        RECT 564.610 895.720 569.750 896.650 ;
        RECT 570.590 895.720 575.730 896.650 ;
        RECT 576.570 895.720 581.710 896.650 ;
        RECT 582.550 895.720 587.690 896.650 ;
        RECT 588.530 895.720 593.670 896.650 ;
        RECT 594.510 895.720 599.650 896.650 ;
        RECT 600.490 895.720 605.630 896.650 ;
        RECT 606.470 895.720 611.610 896.650 ;
        RECT 612.450 895.720 617.590 896.650 ;
        RECT 618.430 895.720 623.570 896.650 ;
        RECT 624.410 895.720 629.550 896.650 ;
        RECT 630.390 895.720 635.530 896.650 ;
        RECT 636.370 895.720 641.510 896.650 ;
        RECT 642.350 895.720 645.280 896.650 ;
        RECT 0.100 10.695 645.280 895.720 ;
      LAYER met3 ;
        RECT 0.270 849.680 646.000 888.585 ;
        RECT 4.400 848.280 646.000 849.680 ;
        RECT 0.270 845.600 646.000 848.280 ;
        RECT 4.400 844.200 646.000 845.600 ;
        RECT 0.270 841.520 646.000 844.200 ;
        RECT 4.400 840.120 646.000 841.520 ;
        RECT 0.270 837.440 646.000 840.120 ;
        RECT 4.400 836.040 646.000 837.440 ;
        RECT 0.270 833.360 646.000 836.040 ;
        RECT 4.400 831.960 645.600 833.360 ;
        RECT 0.270 829.280 646.000 831.960 ;
        RECT 4.400 827.920 646.000 829.280 ;
        RECT 4.400 827.880 645.600 827.920 ;
        RECT 0.270 826.520 645.600 827.880 ;
        RECT 0.270 825.200 646.000 826.520 ;
        RECT 4.400 823.800 646.000 825.200 ;
        RECT 0.270 822.480 646.000 823.800 ;
        RECT 0.270 821.120 645.600 822.480 ;
        RECT 4.400 821.080 645.600 821.120 ;
        RECT 4.400 819.720 646.000 821.080 ;
        RECT 0.270 817.040 646.000 819.720 ;
        RECT 4.400 815.640 645.600 817.040 ;
        RECT 0.270 812.960 646.000 815.640 ;
        RECT 4.400 811.600 646.000 812.960 ;
        RECT 4.400 811.560 645.600 811.600 ;
        RECT 0.270 810.200 645.600 811.560 ;
        RECT 0.270 808.880 646.000 810.200 ;
        RECT 4.400 807.480 646.000 808.880 ;
        RECT 0.270 806.160 646.000 807.480 ;
        RECT 0.270 804.800 645.600 806.160 ;
        RECT 4.400 804.760 645.600 804.800 ;
        RECT 4.400 803.400 646.000 804.760 ;
        RECT 0.270 800.720 646.000 803.400 ;
        RECT 4.400 799.320 645.600 800.720 ;
        RECT 0.270 796.640 646.000 799.320 ;
        RECT 4.400 795.280 646.000 796.640 ;
        RECT 4.400 795.240 645.600 795.280 ;
        RECT 0.270 793.880 645.600 795.240 ;
        RECT 0.270 792.560 646.000 793.880 ;
        RECT 4.400 791.160 646.000 792.560 ;
        RECT 0.270 789.840 646.000 791.160 ;
        RECT 0.270 788.480 645.600 789.840 ;
        RECT 4.400 788.440 645.600 788.480 ;
        RECT 4.400 787.080 646.000 788.440 ;
        RECT 0.270 784.400 646.000 787.080 ;
        RECT 4.400 783.000 645.600 784.400 ;
        RECT 0.270 780.320 646.000 783.000 ;
        RECT 4.400 778.960 646.000 780.320 ;
        RECT 4.400 778.920 645.600 778.960 ;
        RECT 0.270 777.560 645.600 778.920 ;
        RECT 0.270 776.240 646.000 777.560 ;
        RECT 4.400 774.840 646.000 776.240 ;
        RECT 0.270 773.520 646.000 774.840 ;
        RECT 0.270 772.160 645.600 773.520 ;
        RECT 4.400 772.120 645.600 772.160 ;
        RECT 4.400 770.760 646.000 772.120 ;
        RECT 0.270 768.080 646.000 770.760 ;
        RECT 4.400 766.680 645.600 768.080 ;
        RECT 0.270 764.000 646.000 766.680 ;
        RECT 4.400 762.640 646.000 764.000 ;
        RECT 4.400 762.600 645.600 762.640 ;
        RECT 0.270 761.240 645.600 762.600 ;
        RECT 0.270 759.920 646.000 761.240 ;
        RECT 4.400 758.520 646.000 759.920 ;
        RECT 0.270 757.200 646.000 758.520 ;
        RECT 0.270 755.840 645.600 757.200 ;
        RECT 4.400 755.800 645.600 755.840 ;
        RECT 4.400 754.440 646.000 755.800 ;
        RECT 0.270 751.760 646.000 754.440 ;
        RECT 4.400 750.360 645.600 751.760 ;
        RECT 0.270 747.680 646.000 750.360 ;
        RECT 4.400 746.320 646.000 747.680 ;
        RECT 4.400 746.280 645.600 746.320 ;
        RECT 0.270 744.920 645.600 746.280 ;
        RECT 0.270 743.600 646.000 744.920 ;
        RECT 4.400 742.200 646.000 743.600 ;
        RECT 0.270 740.880 646.000 742.200 ;
        RECT 0.270 739.520 645.600 740.880 ;
        RECT 4.400 739.480 645.600 739.520 ;
        RECT 4.400 738.120 646.000 739.480 ;
        RECT 0.270 735.440 646.000 738.120 ;
        RECT 4.400 734.040 645.600 735.440 ;
        RECT 0.270 731.360 646.000 734.040 ;
        RECT 4.400 730.000 646.000 731.360 ;
        RECT 4.400 729.960 645.600 730.000 ;
        RECT 0.270 728.600 645.600 729.960 ;
        RECT 0.270 727.280 646.000 728.600 ;
        RECT 4.400 725.880 646.000 727.280 ;
        RECT 0.270 724.560 646.000 725.880 ;
        RECT 0.270 723.200 645.600 724.560 ;
        RECT 4.400 723.160 645.600 723.200 ;
        RECT 4.400 721.800 646.000 723.160 ;
        RECT 0.270 719.120 646.000 721.800 ;
        RECT 4.400 717.720 645.600 719.120 ;
        RECT 0.270 715.040 646.000 717.720 ;
        RECT 4.400 713.680 646.000 715.040 ;
        RECT 4.400 713.640 645.600 713.680 ;
        RECT 0.270 712.280 645.600 713.640 ;
        RECT 0.270 710.960 646.000 712.280 ;
        RECT 4.400 709.560 646.000 710.960 ;
        RECT 0.270 708.240 646.000 709.560 ;
        RECT 0.270 706.880 645.600 708.240 ;
        RECT 4.400 706.840 645.600 706.880 ;
        RECT 4.400 705.480 646.000 706.840 ;
        RECT 0.270 702.800 646.000 705.480 ;
        RECT 4.400 701.400 645.600 702.800 ;
        RECT 0.270 698.720 646.000 701.400 ;
        RECT 4.400 697.360 646.000 698.720 ;
        RECT 4.400 697.320 645.600 697.360 ;
        RECT 0.270 695.960 645.600 697.320 ;
        RECT 0.270 694.640 646.000 695.960 ;
        RECT 4.400 693.240 646.000 694.640 ;
        RECT 0.270 691.920 646.000 693.240 ;
        RECT 0.270 690.560 645.600 691.920 ;
        RECT 4.400 690.520 645.600 690.560 ;
        RECT 4.400 689.160 646.000 690.520 ;
        RECT 0.270 686.480 646.000 689.160 ;
        RECT 4.400 685.080 645.600 686.480 ;
        RECT 0.270 682.400 646.000 685.080 ;
        RECT 4.400 681.040 646.000 682.400 ;
        RECT 4.400 681.000 645.600 681.040 ;
        RECT 0.270 679.640 645.600 681.000 ;
        RECT 0.270 678.320 646.000 679.640 ;
        RECT 4.400 676.920 646.000 678.320 ;
        RECT 0.270 675.600 646.000 676.920 ;
        RECT 0.270 674.240 645.600 675.600 ;
        RECT 4.400 674.200 645.600 674.240 ;
        RECT 4.400 672.840 646.000 674.200 ;
        RECT 0.270 670.160 646.000 672.840 ;
        RECT 4.400 668.760 645.600 670.160 ;
        RECT 0.270 666.080 646.000 668.760 ;
        RECT 4.400 664.720 646.000 666.080 ;
        RECT 4.400 664.680 645.600 664.720 ;
        RECT 0.270 663.320 645.600 664.680 ;
        RECT 0.270 662.000 646.000 663.320 ;
        RECT 4.400 660.600 646.000 662.000 ;
        RECT 0.270 659.280 646.000 660.600 ;
        RECT 0.270 657.920 645.600 659.280 ;
        RECT 4.400 657.880 645.600 657.920 ;
        RECT 4.400 656.520 646.000 657.880 ;
        RECT 0.270 653.840 646.000 656.520 ;
        RECT 4.400 652.440 645.600 653.840 ;
        RECT 0.270 649.760 646.000 652.440 ;
        RECT 4.400 648.400 646.000 649.760 ;
        RECT 4.400 648.360 645.600 648.400 ;
        RECT 0.270 647.000 645.600 648.360 ;
        RECT 0.270 645.680 646.000 647.000 ;
        RECT 4.400 644.280 646.000 645.680 ;
        RECT 0.270 642.960 646.000 644.280 ;
        RECT 0.270 641.600 645.600 642.960 ;
        RECT 4.400 641.560 645.600 641.600 ;
        RECT 4.400 640.200 646.000 641.560 ;
        RECT 0.270 637.520 646.000 640.200 ;
        RECT 4.400 636.120 645.600 637.520 ;
        RECT 0.270 633.440 646.000 636.120 ;
        RECT 4.400 632.080 646.000 633.440 ;
        RECT 4.400 632.040 645.600 632.080 ;
        RECT 0.270 630.680 645.600 632.040 ;
        RECT 0.270 629.360 646.000 630.680 ;
        RECT 4.400 627.960 646.000 629.360 ;
        RECT 0.270 626.640 646.000 627.960 ;
        RECT 0.270 625.280 645.600 626.640 ;
        RECT 4.400 625.240 645.600 625.280 ;
        RECT 4.400 623.880 646.000 625.240 ;
        RECT 0.270 621.200 646.000 623.880 ;
        RECT 4.400 619.800 645.600 621.200 ;
        RECT 0.270 617.120 646.000 619.800 ;
        RECT 4.400 615.760 646.000 617.120 ;
        RECT 4.400 615.720 645.600 615.760 ;
        RECT 0.270 614.360 645.600 615.720 ;
        RECT 0.270 613.040 646.000 614.360 ;
        RECT 4.400 611.640 646.000 613.040 ;
        RECT 0.270 610.320 646.000 611.640 ;
        RECT 0.270 608.960 645.600 610.320 ;
        RECT 4.400 608.920 645.600 608.960 ;
        RECT 4.400 607.560 646.000 608.920 ;
        RECT 0.270 604.880 646.000 607.560 ;
        RECT 4.400 603.480 645.600 604.880 ;
        RECT 0.270 600.800 646.000 603.480 ;
        RECT 4.400 599.440 646.000 600.800 ;
        RECT 4.400 599.400 645.600 599.440 ;
        RECT 0.270 598.040 645.600 599.400 ;
        RECT 0.270 596.720 646.000 598.040 ;
        RECT 4.400 595.320 646.000 596.720 ;
        RECT 0.270 594.000 646.000 595.320 ;
        RECT 0.270 592.640 645.600 594.000 ;
        RECT 4.400 592.600 645.600 592.640 ;
        RECT 4.400 591.240 646.000 592.600 ;
        RECT 0.270 588.560 646.000 591.240 ;
        RECT 4.400 587.160 645.600 588.560 ;
        RECT 0.270 584.480 646.000 587.160 ;
        RECT 4.400 583.120 646.000 584.480 ;
        RECT 4.400 583.080 645.600 583.120 ;
        RECT 0.270 581.720 645.600 583.080 ;
        RECT 0.270 580.400 646.000 581.720 ;
        RECT 4.400 579.000 646.000 580.400 ;
        RECT 0.270 577.680 646.000 579.000 ;
        RECT 0.270 576.320 645.600 577.680 ;
        RECT 4.400 576.280 645.600 576.320 ;
        RECT 4.400 574.920 646.000 576.280 ;
        RECT 0.270 572.240 646.000 574.920 ;
        RECT 4.400 570.840 645.600 572.240 ;
        RECT 0.270 568.160 646.000 570.840 ;
        RECT 4.400 566.800 646.000 568.160 ;
        RECT 4.400 566.760 645.600 566.800 ;
        RECT 0.270 565.400 645.600 566.760 ;
        RECT 0.270 564.080 646.000 565.400 ;
        RECT 4.400 562.680 646.000 564.080 ;
        RECT 0.270 561.360 646.000 562.680 ;
        RECT 0.270 560.000 645.600 561.360 ;
        RECT 4.400 559.960 645.600 560.000 ;
        RECT 4.400 558.600 646.000 559.960 ;
        RECT 0.270 555.920 646.000 558.600 ;
        RECT 4.400 554.520 645.600 555.920 ;
        RECT 0.270 551.840 646.000 554.520 ;
        RECT 4.400 550.480 646.000 551.840 ;
        RECT 4.400 550.440 645.600 550.480 ;
        RECT 0.270 549.080 645.600 550.440 ;
        RECT 0.270 547.760 646.000 549.080 ;
        RECT 4.400 546.360 646.000 547.760 ;
        RECT 0.270 545.040 646.000 546.360 ;
        RECT 0.270 543.680 645.600 545.040 ;
        RECT 4.400 543.640 645.600 543.680 ;
        RECT 4.400 542.280 646.000 543.640 ;
        RECT 0.270 539.600 646.000 542.280 ;
        RECT 4.400 538.200 645.600 539.600 ;
        RECT 0.270 535.520 646.000 538.200 ;
        RECT 4.400 534.160 646.000 535.520 ;
        RECT 4.400 534.120 645.600 534.160 ;
        RECT 0.270 532.760 645.600 534.120 ;
        RECT 0.270 531.440 646.000 532.760 ;
        RECT 4.400 530.040 646.000 531.440 ;
        RECT 0.270 528.720 646.000 530.040 ;
        RECT 0.270 527.360 645.600 528.720 ;
        RECT 4.400 527.320 645.600 527.360 ;
        RECT 4.400 525.960 646.000 527.320 ;
        RECT 0.270 523.280 646.000 525.960 ;
        RECT 4.400 521.880 645.600 523.280 ;
        RECT 0.270 519.200 646.000 521.880 ;
        RECT 4.400 517.840 646.000 519.200 ;
        RECT 4.400 517.800 645.600 517.840 ;
        RECT 0.270 516.440 645.600 517.800 ;
        RECT 0.270 515.120 646.000 516.440 ;
        RECT 4.400 513.720 646.000 515.120 ;
        RECT 0.270 512.400 646.000 513.720 ;
        RECT 0.270 511.040 645.600 512.400 ;
        RECT 4.400 511.000 645.600 511.040 ;
        RECT 4.400 509.640 646.000 511.000 ;
        RECT 0.270 506.960 646.000 509.640 ;
        RECT 4.400 505.560 645.600 506.960 ;
        RECT 0.270 502.880 646.000 505.560 ;
        RECT 4.400 501.520 646.000 502.880 ;
        RECT 4.400 501.480 645.600 501.520 ;
        RECT 0.270 500.120 645.600 501.480 ;
        RECT 0.270 498.800 646.000 500.120 ;
        RECT 4.400 497.400 646.000 498.800 ;
        RECT 0.270 496.080 646.000 497.400 ;
        RECT 0.270 494.720 645.600 496.080 ;
        RECT 4.400 494.680 645.600 494.720 ;
        RECT 4.400 493.320 646.000 494.680 ;
        RECT 0.270 490.640 646.000 493.320 ;
        RECT 4.400 489.240 645.600 490.640 ;
        RECT 0.270 486.560 646.000 489.240 ;
        RECT 4.400 485.200 646.000 486.560 ;
        RECT 4.400 485.160 645.600 485.200 ;
        RECT 0.270 483.800 645.600 485.160 ;
        RECT 0.270 482.480 646.000 483.800 ;
        RECT 4.400 481.080 646.000 482.480 ;
        RECT 0.270 479.760 646.000 481.080 ;
        RECT 0.270 478.400 645.600 479.760 ;
        RECT 4.400 478.360 645.600 478.400 ;
        RECT 4.400 477.000 646.000 478.360 ;
        RECT 0.270 474.320 646.000 477.000 ;
        RECT 4.400 472.920 645.600 474.320 ;
        RECT 0.270 470.240 646.000 472.920 ;
        RECT 4.400 468.880 646.000 470.240 ;
        RECT 4.400 468.840 645.600 468.880 ;
        RECT 0.270 467.480 645.600 468.840 ;
        RECT 0.270 466.160 646.000 467.480 ;
        RECT 4.400 464.760 646.000 466.160 ;
        RECT 0.270 463.440 646.000 464.760 ;
        RECT 0.270 462.080 645.600 463.440 ;
        RECT 4.400 462.040 645.600 462.080 ;
        RECT 4.400 460.680 646.000 462.040 ;
        RECT 0.270 458.000 646.000 460.680 ;
        RECT 4.400 456.600 645.600 458.000 ;
        RECT 0.270 453.920 646.000 456.600 ;
        RECT 4.400 452.560 646.000 453.920 ;
        RECT 4.400 452.520 645.600 452.560 ;
        RECT 0.270 451.160 645.600 452.520 ;
        RECT 0.270 449.840 646.000 451.160 ;
        RECT 4.400 448.440 646.000 449.840 ;
        RECT 0.270 447.120 646.000 448.440 ;
        RECT 0.270 445.760 645.600 447.120 ;
        RECT 4.400 445.720 645.600 445.760 ;
        RECT 4.400 444.360 646.000 445.720 ;
        RECT 0.270 441.680 646.000 444.360 ;
        RECT 4.400 440.280 645.600 441.680 ;
        RECT 0.270 437.600 646.000 440.280 ;
        RECT 4.400 436.240 646.000 437.600 ;
        RECT 4.400 436.200 645.600 436.240 ;
        RECT 0.270 434.840 645.600 436.200 ;
        RECT 0.270 433.520 646.000 434.840 ;
        RECT 4.400 432.120 646.000 433.520 ;
        RECT 0.270 430.800 646.000 432.120 ;
        RECT 0.270 429.440 645.600 430.800 ;
        RECT 4.400 429.400 645.600 429.440 ;
        RECT 4.400 428.040 646.000 429.400 ;
        RECT 0.270 425.360 646.000 428.040 ;
        RECT 4.400 423.960 645.600 425.360 ;
        RECT 0.270 421.280 646.000 423.960 ;
        RECT 4.400 419.920 646.000 421.280 ;
        RECT 4.400 419.880 645.600 419.920 ;
        RECT 0.270 418.520 645.600 419.880 ;
        RECT 0.270 417.200 646.000 418.520 ;
        RECT 4.400 415.800 646.000 417.200 ;
        RECT 0.270 414.480 646.000 415.800 ;
        RECT 0.270 413.120 645.600 414.480 ;
        RECT 4.400 413.080 645.600 413.120 ;
        RECT 4.400 411.720 646.000 413.080 ;
        RECT 0.270 409.040 646.000 411.720 ;
        RECT 4.400 407.640 645.600 409.040 ;
        RECT 0.270 404.960 646.000 407.640 ;
        RECT 4.400 403.600 646.000 404.960 ;
        RECT 4.400 403.560 645.600 403.600 ;
        RECT 0.270 402.200 645.600 403.560 ;
        RECT 0.270 400.880 646.000 402.200 ;
        RECT 4.400 399.480 646.000 400.880 ;
        RECT 0.270 398.160 646.000 399.480 ;
        RECT 0.270 396.800 645.600 398.160 ;
        RECT 4.400 396.760 645.600 396.800 ;
        RECT 4.400 395.400 646.000 396.760 ;
        RECT 0.270 392.720 646.000 395.400 ;
        RECT 4.400 391.320 645.600 392.720 ;
        RECT 0.270 388.640 646.000 391.320 ;
        RECT 4.400 387.280 646.000 388.640 ;
        RECT 4.400 387.240 645.600 387.280 ;
        RECT 0.270 385.880 645.600 387.240 ;
        RECT 0.270 384.560 646.000 385.880 ;
        RECT 4.400 383.160 646.000 384.560 ;
        RECT 0.270 381.840 646.000 383.160 ;
        RECT 0.270 380.480 645.600 381.840 ;
        RECT 4.400 380.440 645.600 380.480 ;
        RECT 4.400 379.080 646.000 380.440 ;
        RECT 0.270 376.400 646.000 379.080 ;
        RECT 4.400 375.000 645.600 376.400 ;
        RECT 0.270 372.320 646.000 375.000 ;
        RECT 4.400 370.960 646.000 372.320 ;
        RECT 4.400 370.920 645.600 370.960 ;
        RECT 0.270 369.560 645.600 370.920 ;
        RECT 0.270 368.240 646.000 369.560 ;
        RECT 4.400 366.840 646.000 368.240 ;
        RECT 0.270 365.520 646.000 366.840 ;
        RECT 0.270 364.160 645.600 365.520 ;
        RECT 4.400 364.120 645.600 364.160 ;
        RECT 4.400 362.760 646.000 364.120 ;
        RECT 0.270 360.080 646.000 362.760 ;
        RECT 4.400 358.680 645.600 360.080 ;
        RECT 0.270 356.000 646.000 358.680 ;
        RECT 4.400 354.640 646.000 356.000 ;
        RECT 4.400 354.600 645.600 354.640 ;
        RECT 0.270 353.240 645.600 354.600 ;
        RECT 0.270 351.920 646.000 353.240 ;
        RECT 4.400 350.520 646.000 351.920 ;
        RECT 0.270 349.200 646.000 350.520 ;
        RECT 0.270 347.840 645.600 349.200 ;
        RECT 4.400 347.800 645.600 347.840 ;
        RECT 4.400 346.440 646.000 347.800 ;
        RECT 0.270 343.760 646.000 346.440 ;
        RECT 4.400 342.360 645.600 343.760 ;
        RECT 0.270 339.680 646.000 342.360 ;
        RECT 4.400 338.320 646.000 339.680 ;
        RECT 4.400 338.280 645.600 338.320 ;
        RECT 0.270 336.920 645.600 338.280 ;
        RECT 0.270 335.600 646.000 336.920 ;
        RECT 4.400 334.200 646.000 335.600 ;
        RECT 0.270 332.880 646.000 334.200 ;
        RECT 0.270 331.520 645.600 332.880 ;
        RECT 4.400 331.480 645.600 331.520 ;
        RECT 4.400 330.120 646.000 331.480 ;
        RECT 0.270 327.440 646.000 330.120 ;
        RECT 4.400 326.040 645.600 327.440 ;
        RECT 0.270 323.360 646.000 326.040 ;
        RECT 4.400 322.000 646.000 323.360 ;
        RECT 4.400 321.960 645.600 322.000 ;
        RECT 0.270 320.600 645.600 321.960 ;
        RECT 0.270 319.280 646.000 320.600 ;
        RECT 4.400 317.880 646.000 319.280 ;
        RECT 0.270 316.560 646.000 317.880 ;
        RECT 0.270 315.200 645.600 316.560 ;
        RECT 4.400 315.160 645.600 315.200 ;
        RECT 4.400 313.800 646.000 315.160 ;
        RECT 0.270 311.120 646.000 313.800 ;
        RECT 4.400 309.720 645.600 311.120 ;
        RECT 0.270 307.040 646.000 309.720 ;
        RECT 4.400 305.680 646.000 307.040 ;
        RECT 4.400 305.640 645.600 305.680 ;
        RECT 0.270 304.280 645.600 305.640 ;
        RECT 0.270 302.960 646.000 304.280 ;
        RECT 4.400 301.560 646.000 302.960 ;
        RECT 0.270 300.240 646.000 301.560 ;
        RECT 0.270 298.880 645.600 300.240 ;
        RECT 4.400 298.840 645.600 298.880 ;
        RECT 4.400 297.480 646.000 298.840 ;
        RECT 0.270 294.800 646.000 297.480 ;
        RECT 4.400 293.400 645.600 294.800 ;
        RECT 0.270 290.720 646.000 293.400 ;
        RECT 4.400 289.360 646.000 290.720 ;
        RECT 4.400 289.320 645.600 289.360 ;
        RECT 0.270 287.960 645.600 289.320 ;
        RECT 0.270 286.640 646.000 287.960 ;
        RECT 4.400 285.240 646.000 286.640 ;
        RECT 0.270 283.920 646.000 285.240 ;
        RECT 0.270 282.560 645.600 283.920 ;
        RECT 4.400 282.520 645.600 282.560 ;
        RECT 4.400 281.160 646.000 282.520 ;
        RECT 0.270 278.480 646.000 281.160 ;
        RECT 4.400 277.080 645.600 278.480 ;
        RECT 0.270 274.400 646.000 277.080 ;
        RECT 4.400 273.040 646.000 274.400 ;
        RECT 4.400 273.000 645.600 273.040 ;
        RECT 0.270 271.640 645.600 273.000 ;
        RECT 0.270 270.320 646.000 271.640 ;
        RECT 4.400 268.920 646.000 270.320 ;
        RECT 0.270 267.600 646.000 268.920 ;
        RECT 0.270 266.240 645.600 267.600 ;
        RECT 4.400 266.200 645.600 266.240 ;
        RECT 4.400 264.840 646.000 266.200 ;
        RECT 0.270 262.160 646.000 264.840 ;
        RECT 4.400 260.760 645.600 262.160 ;
        RECT 0.270 258.080 646.000 260.760 ;
        RECT 4.400 256.720 646.000 258.080 ;
        RECT 4.400 256.680 645.600 256.720 ;
        RECT 0.270 255.320 645.600 256.680 ;
        RECT 0.270 254.000 646.000 255.320 ;
        RECT 4.400 252.600 646.000 254.000 ;
        RECT 0.270 251.280 646.000 252.600 ;
        RECT 0.270 249.920 645.600 251.280 ;
        RECT 4.400 249.880 645.600 249.920 ;
        RECT 4.400 248.520 646.000 249.880 ;
        RECT 0.270 245.840 646.000 248.520 ;
        RECT 4.400 244.440 645.600 245.840 ;
        RECT 0.270 241.760 646.000 244.440 ;
        RECT 4.400 240.400 646.000 241.760 ;
        RECT 4.400 240.360 645.600 240.400 ;
        RECT 0.270 239.000 645.600 240.360 ;
        RECT 0.270 237.680 646.000 239.000 ;
        RECT 4.400 236.280 646.000 237.680 ;
        RECT 0.270 234.960 646.000 236.280 ;
        RECT 0.270 233.600 645.600 234.960 ;
        RECT 4.400 233.560 645.600 233.600 ;
        RECT 4.400 232.200 646.000 233.560 ;
        RECT 0.270 229.520 646.000 232.200 ;
        RECT 4.400 228.120 645.600 229.520 ;
        RECT 0.270 225.440 646.000 228.120 ;
        RECT 4.400 224.080 646.000 225.440 ;
        RECT 4.400 224.040 645.600 224.080 ;
        RECT 0.270 222.680 645.600 224.040 ;
        RECT 0.270 221.360 646.000 222.680 ;
        RECT 4.400 219.960 646.000 221.360 ;
        RECT 0.270 218.640 646.000 219.960 ;
        RECT 0.270 217.280 645.600 218.640 ;
        RECT 4.400 217.240 645.600 217.280 ;
        RECT 4.400 215.880 646.000 217.240 ;
        RECT 0.270 213.200 646.000 215.880 ;
        RECT 4.400 211.800 645.600 213.200 ;
        RECT 0.270 209.120 646.000 211.800 ;
        RECT 4.400 207.760 646.000 209.120 ;
        RECT 4.400 207.720 645.600 207.760 ;
        RECT 0.270 206.360 645.600 207.720 ;
        RECT 0.270 205.040 646.000 206.360 ;
        RECT 4.400 203.640 646.000 205.040 ;
        RECT 0.270 202.320 646.000 203.640 ;
        RECT 0.270 200.960 645.600 202.320 ;
        RECT 4.400 200.920 645.600 200.960 ;
        RECT 4.400 199.560 646.000 200.920 ;
        RECT 0.270 196.880 646.000 199.560 ;
        RECT 4.400 195.480 645.600 196.880 ;
        RECT 0.270 192.800 646.000 195.480 ;
        RECT 4.400 191.440 646.000 192.800 ;
        RECT 4.400 191.400 645.600 191.440 ;
        RECT 0.270 190.040 645.600 191.400 ;
        RECT 0.270 188.720 646.000 190.040 ;
        RECT 4.400 187.320 646.000 188.720 ;
        RECT 0.270 186.000 646.000 187.320 ;
        RECT 0.270 184.640 645.600 186.000 ;
        RECT 4.400 184.600 645.600 184.640 ;
        RECT 4.400 183.240 646.000 184.600 ;
        RECT 0.270 180.560 646.000 183.240 ;
        RECT 4.400 179.160 645.600 180.560 ;
        RECT 0.270 176.480 646.000 179.160 ;
        RECT 4.400 175.120 646.000 176.480 ;
        RECT 4.400 175.080 645.600 175.120 ;
        RECT 0.270 173.720 645.600 175.080 ;
        RECT 0.270 172.400 646.000 173.720 ;
        RECT 4.400 171.000 646.000 172.400 ;
        RECT 0.270 169.680 646.000 171.000 ;
        RECT 0.270 168.320 645.600 169.680 ;
        RECT 4.400 168.280 645.600 168.320 ;
        RECT 4.400 166.920 646.000 168.280 ;
        RECT 0.270 164.240 646.000 166.920 ;
        RECT 4.400 162.840 645.600 164.240 ;
        RECT 0.270 160.160 646.000 162.840 ;
        RECT 4.400 158.800 646.000 160.160 ;
        RECT 4.400 158.760 645.600 158.800 ;
        RECT 0.270 157.400 645.600 158.760 ;
        RECT 0.270 156.080 646.000 157.400 ;
        RECT 4.400 154.680 646.000 156.080 ;
        RECT 0.270 153.360 646.000 154.680 ;
        RECT 0.270 152.000 645.600 153.360 ;
        RECT 4.400 151.960 645.600 152.000 ;
        RECT 4.400 150.600 646.000 151.960 ;
        RECT 0.270 147.920 646.000 150.600 ;
        RECT 4.400 146.520 645.600 147.920 ;
        RECT 0.270 143.840 646.000 146.520 ;
        RECT 4.400 142.480 646.000 143.840 ;
        RECT 4.400 142.440 645.600 142.480 ;
        RECT 0.270 141.080 645.600 142.440 ;
        RECT 0.270 139.760 646.000 141.080 ;
        RECT 4.400 138.360 646.000 139.760 ;
        RECT 0.270 137.040 646.000 138.360 ;
        RECT 0.270 135.680 645.600 137.040 ;
        RECT 4.400 135.640 645.600 135.680 ;
        RECT 4.400 134.280 646.000 135.640 ;
        RECT 0.270 131.600 646.000 134.280 ;
        RECT 4.400 130.200 645.600 131.600 ;
        RECT 0.270 127.520 646.000 130.200 ;
        RECT 4.400 126.160 646.000 127.520 ;
        RECT 4.400 126.120 645.600 126.160 ;
        RECT 0.270 124.760 645.600 126.120 ;
        RECT 0.270 123.440 646.000 124.760 ;
        RECT 4.400 122.040 646.000 123.440 ;
        RECT 0.270 120.720 646.000 122.040 ;
        RECT 0.270 119.360 645.600 120.720 ;
        RECT 4.400 119.320 645.600 119.360 ;
        RECT 4.400 117.960 646.000 119.320 ;
        RECT 0.270 115.280 646.000 117.960 ;
        RECT 4.400 113.880 645.600 115.280 ;
        RECT 0.270 111.200 646.000 113.880 ;
        RECT 4.400 109.840 646.000 111.200 ;
        RECT 4.400 109.800 645.600 109.840 ;
        RECT 0.270 108.440 645.600 109.800 ;
        RECT 0.270 107.120 646.000 108.440 ;
        RECT 4.400 105.720 646.000 107.120 ;
        RECT 0.270 104.400 646.000 105.720 ;
        RECT 0.270 103.040 645.600 104.400 ;
        RECT 4.400 103.000 645.600 103.040 ;
        RECT 4.400 101.640 646.000 103.000 ;
        RECT 0.270 98.960 646.000 101.640 ;
        RECT 4.400 97.560 645.600 98.960 ;
        RECT 0.270 94.880 646.000 97.560 ;
        RECT 4.400 93.520 646.000 94.880 ;
        RECT 4.400 93.480 645.600 93.520 ;
        RECT 0.270 92.120 645.600 93.480 ;
        RECT 0.270 90.800 646.000 92.120 ;
        RECT 4.400 89.400 646.000 90.800 ;
        RECT 0.270 88.080 646.000 89.400 ;
        RECT 0.270 86.720 645.600 88.080 ;
        RECT 4.400 86.680 645.600 86.720 ;
        RECT 4.400 85.320 646.000 86.680 ;
        RECT 0.270 82.640 646.000 85.320 ;
        RECT 4.400 81.240 645.600 82.640 ;
        RECT 0.270 78.560 646.000 81.240 ;
        RECT 4.400 77.200 646.000 78.560 ;
        RECT 4.400 77.160 645.600 77.200 ;
        RECT 0.270 75.800 645.600 77.160 ;
        RECT 0.270 74.480 646.000 75.800 ;
        RECT 4.400 73.080 646.000 74.480 ;
        RECT 0.270 71.760 646.000 73.080 ;
        RECT 0.270 70.400 645.600 71.760 ;
        RECT 4.400 70.360 645.600 70.400 ;
        RECT 4.400 69.000 646.000 70.360 ;
        RECT 0.270 66.320 646.000 69.000 ;
        RECT 4.400 64.920 645.600 66.320 ;
        RECT 0.270 62.240 646.000 64.920 ;
        RECT 4.400 60.840 646.000 62.240 ;
        RECT 0.270 58.160 646.000 60.840 ;
        RECT 4.400 56.760 646.000 58.160 ;
        RECT 0.270 54.080 646.000 56.760 ;
        RECT 4.400 52.680 646.000 54.080 ;
        RECT 0.270 50.000 646.000 52.680 ;
        RECT 4.400 48.600 646.000 50.000 ;
        RECT 0.270 10.715 646.000 48.600 ;
      LAYER met4 ;
        RECT 0.295 31.455 20.640 884.505 ;
        RECT 23.040 31.455 23.940 884.505 ;
        RECT 26.340 31.455 174.240 884.505 ;
        RECT 176.640 490.300 177.540 884.505 ;
        RECT 179.940 490.300 327.840 884.505 ;
        RECT 330.240 490.300 331.140 884.505 ;
        RECT 333.540 490.300 481.440 884.505 ;
        RECT 176.640 39.700 481.440 490.300 ;
        RECT 176.640 31.455 177.540 39.700 ;
        RECT 179.940 31.455 327.840 39.700 ;
        RECT 330.240 31.455 331.140 39.700 ;
        RECT 333.540 31.455 481.440 39.700 ;
        RECT 483.840 31.455 484.740 884.505 ;
        RECT 487.140 31.455 635.040 884.505 ;
        RECT 637.440 31.455 638.185 884.505 ;
  END
END core_controller_wrapper_m
END LIBRARY

